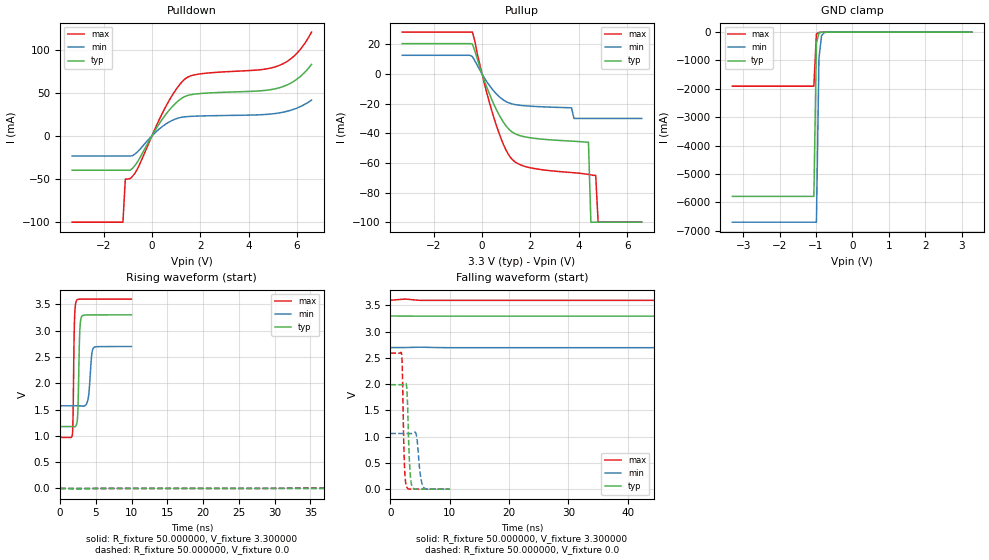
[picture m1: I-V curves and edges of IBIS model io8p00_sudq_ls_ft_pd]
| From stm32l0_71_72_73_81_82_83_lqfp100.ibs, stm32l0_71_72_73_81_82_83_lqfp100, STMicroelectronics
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|   Model io8p00_sudq_ls_ft_pd
[Model]  io8p00_sudq_ls_ft_pd
Model_type I/O
Polarity   Non-Inverting
Enable   Active-Low
Vinl =   0.990000V
Vinh =   2.310000V
Vmeas =  1.650000V
Cref =   50.000000pF
Rref =   100.000000M
Vref =   0.0V
C_comp   2.343000pF   2.309800pF   2.393900pF
[Temperature Range]   25.000000   0.125000k   -40.000000
[Pullup Reference]   3.300000V   2.700000V   3.600000V
[Pulldown Reference]   0.0V   0.0V   0.0V
[POWER Clamp Reference]   3.300000V   2.700000V   3.600000V
[GND Clamp Reference]   0.0V   0.0V   0.0V
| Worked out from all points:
|   slope of the pulldown table from 0 to 0.495 V, typ, clamps not added: 22.6 ohm
|   slope of the pullup table from 0 to 0.495 V, typ, clamps not added: 23.9 ohm
|   GND clamp passes 1 mA (typ) near -0.64 V on its own axis
|   rising waveform, R_fixture 50.000000, V_fixture 3.300000: 20-80 % time 207ps typ, 362ps min, 164ps max; typ from 1.18 V to 3.3 V
|   rising waveform, R_fixture 50.000000, V_fixture 0.0: 20-80 % time 205ns typ, 426ns min, 99.7ns max; typ from 0 V to 1.99 V
|   falling waveform, R_fixture 50.000000, V_fixture 3.300000: 20-80 % time 193ns typ, 381ns min, 106ns max; typ from 3.3 V to 1.18 V
|   falling waveform, R_fixture 50.000000, V_fixture 0.0: 20-80 % time 379ps typ, 551ps min, 301ps max; typ from 1.99 V to 0 V
[Pulldown]
|Voltage   I(typ)   I(min)   I(max)
-3.3V     -39.8mA    -23.38mA   -100mA
-1.2V     -39.8mA    -23.38mA   -100mA
-1.1V     -39.8mA    -23.38mA   -50.11mA
-900mV    -39.8mA    -23.38mA   -49.43mA
-700mV    -34.25mA   -21mA      -43.13mA
600mV     25.84mA    14.18mA    35.34mA
1V        38.32mA    19.82mA    53.81mA
1.4V      46.09mA    22.19mA    66.63mA
2V        49.05mA    23.02mA    71.83mA
5.2V      55.23mA    26.32mA    80.92mA
6V        65.76mA    32.26mA    95.84mA
6.6V      82.81mA    41.43mA    120.2mA
[Pullup]
|Voltage   I(typ)   I(min)   I(max)
-3.3V     20.5mA     12.63mA    28.27mA
-400mV    20.25mA    11.77mA    28.27mA
500mV     -20.88mA   -11.78mA   -30.07mA
1.2V      -38.62mA   -19.99mA   -56.79mA
1.9V      -42.8mA    -21.61mA   -62.92mA
3.7V      -45.29mA   -22.8mA    -66.5mA
3.8V      -45.39mA   -30mA      -66.64mA
4.4V      -46mA      -30mA      -67.77mA
4.5V      -100mA     -30mA      -68.06mA
4.7V      -100mA     -30mA      -68.41mA
4.8V      -100mA     -30mA      -100mA
6.6V      -100mA     -30mA      -100mA
[GND_clamp]
|Voltage   I(typ)   I(min)   I(max)
-3.3V     -5.787A    -6.696A    -1.906A
-1.06V    -5.787A    -6.696A    -1.906A
-990mV    -393.4mA   -6.696A    -70.76mA
-920mV    -33.04mA   -919.4mA   -10.91mA
-850mV    -6.842mA   -131.3mA   -6.529mA
-780mV    -3.49mA    -21.08mA   -4.216mA
3.28V     73.94uA    88.61uA    51.47uA
[POWER_clamp]
|Voltage   I(typ)   I(min)   I(max)
-3.28V    0A         0A         0A
0V        0A         0A         0A
[Ramp]
| variable   typ   min   max
dV/dt_r  1.19406/0.20443u   0.61140/0.42773u   1.55520/99.59326n
dV/dt_f  1.27242/0.19294u   0.63606/0.38172u   1.57766/0.10605u
R_load = 50.000000
[Rising Waveform]
R_fixture= 50.000000
V_fixture= 3.300000
V_fixture_min= 2.700000
V_fixture_max= 3.600000
|time   V(typ)   V(min)   V(max)
0s        1.176V     1.571V     970mV
1.702ns   1.176V     1.571V     1.017V
2.002ns   1.172V     1.571V     3.17V
2.282ns   1.213V     1.571V     3.57V
2.482ns   1.498V     1.571V     3.593V
2.743ns   2.977V     1.569V     3.597V
3.023ns   3.27V      1.566V     3.598V
3.904ns   3.298V     1.7V       3.599V
4.665ns   3.298V     2.67V      3.599V
9.97ns    3.299V     2.698V     3.599V
[Rising Waveform]
R_fixture= 50.000000
V_fixture= 0.0
V_fixture_min= 0.0
V_fixture_max= 0.0
|time   V(typ)   V(min)   V(max)
0s        1.995nV    14.14nV    4.364nV
50.05ns   270.4uV    -21.95uV   84.32mV
102.6ns   83.63mV    140.7uV    950.6mV
165.2ns   449.5mV    2.92mV     1.927V
205.2ns   740.5mV    17.3mV     2.287V
255.3ns   1.082V     53.22mV    2.483V
357.9ns   1.578V     187mV      2.573V
508ns     1.88V      446.8mV    2.591V
818.3ns   1.983V     866.7mV    2.592V
1.246us   1.99V      1.06V      2.592V
[Falling Waveform]
R_fixture= 50.000000
V_fixture= 3.300000
V_fixture_min= 2.700000
V_fixture_max= 3.600000
|time   V(typ)   V(min)   V(max)
0s        3.299V     2.698V     3.599V
85.09ns   3.296V     2.695V     3.473V
145.1ns   3.211V     2.695V     2.592V
212.7ns   2.848V     2.692V     1.602V
250.2ns   2.593V     2.681V     1.235V
285.3ns   2.344V     2.663V     1.089V
397.9ns   1.619V     2.542V     997.6mV
500.5ns   1.332V     2.372V     979.9mV
823.3ns   1.195V     1.797V     970.6mV
1.246us   1.176V     1.571V     970mV
[Falling Waveform]
R_fixture= 50.000000
V_fixture= 0.0
V_fixture_min= 0.0
V_fixture_max= 0.0
|time   V(typ)   V(min)   V(max)
0s        1.99V      1.06V      2.592V
1.922ns   1.99V      1.06V      2.564V
2.022ns   1.99V      1.06V      2.313V
2.382ns   1.995V     1.06V      480.1mV
2.783ns   1.915V     1.06V      38.06mV
3.243ns   503.8mV    1.06V      2.313mV
3.664ns   55.79mV    1.061V     212.5uV
4.404ns   969uV      1.024V     88.3uV
5.546ns   55.3uV     41.9mV     37.89uV
9.97ns    1.995nV    14.14nV    4.364nV
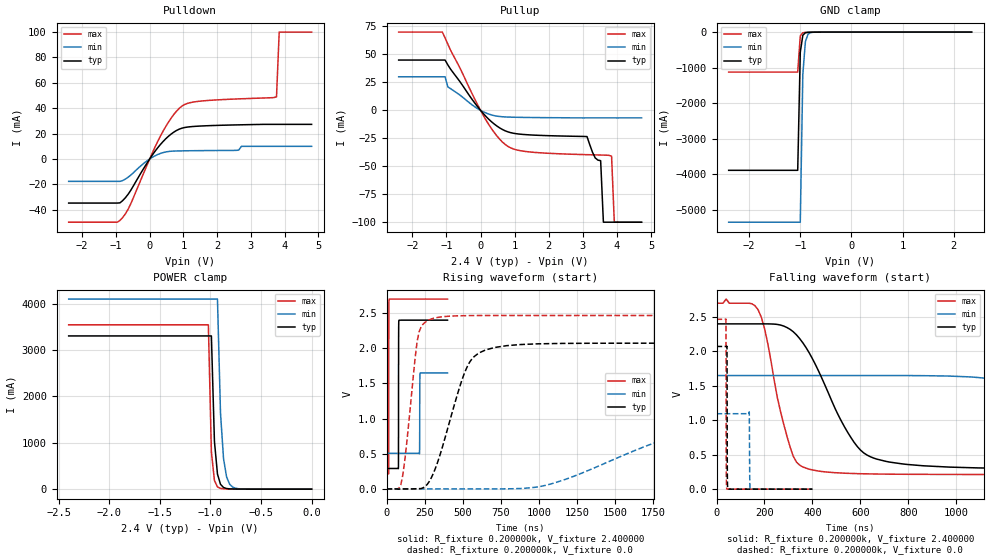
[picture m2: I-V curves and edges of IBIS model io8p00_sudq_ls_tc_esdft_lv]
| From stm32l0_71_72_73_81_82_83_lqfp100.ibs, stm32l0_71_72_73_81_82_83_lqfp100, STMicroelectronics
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|   Model io8p00_sudq_ls_tc_esdft_lv
[Model]  io8p00_sudq_ls_tc_esdft_lv
Model_type I/O
Polarity   Non-Inverting
Enable   Active-Low
Vinl =   0.720000V
Vinh =   1.680000V
Vmeas =  1.200000V
Cref =   50.000000pF
Rref =   100.000000M
Vref =   0.0V
C_comp   2.242700pF   2.201100pF   2.288600pF
[Temperature Range]   25.000000   0.105000k   -40.000000
[Pullup Reference]   2.400000V   1.650000V   2.700000V
[Pulldown Reference]   0.0V   0.0V   0.0V
[POWER Clamp Reference]   2.400000V   1.650000V   2.700000V
[GND Clamp Reference]   0.0V   0.0V   0.0V
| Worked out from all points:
|   slope of the pulldown table from 0 to 0.36 V, typ, clamps not added: 28.4 ohm
|   slope of the pullup table from 0 to 0.36 V, typ, clamps not added: 32.2 ohm
|   GND clamp passes 1 mA (typ) near -0.65 V on its own axis
|   POWER clamp passes 1 mA (typ) near -0.63 V on its own axis
|   rising waveform, R_fixture 0.200000k, V_fixture 2.400000: 20-80 % time 637ps typ, 857ps min, 664ps max; typ from 0.291 V to 2.4 V
|   rising waveform, R_fixture 0.200000k, V_fixture 0.0: 20-80 % time 173ns typ, 833ns min, 69.4ns max; typ from 0 V to 2.07 V
|   falling waveform, R_fixture 0.200000k, V_fixture 2.400000: 20-80 % time 181ns typ, 734ns min, 90.4ns max; typ from 2.4 V to 0.291 V
|   falling waveform, R_fixture 0.200000k, V_fixture 0.0: 20-80 % time 753ps typ, 1.18ns min, 666ps max; typ from 2.07 V to 0 V
[Pulldown]
|Voltage   I(typ)   I(min)   I(max)
-2.4V     -34.7mA    -17.62mA   -49.77mA
-880mV    -34.55mA   -17.62mA   -48.41mA
-560mV    -24.66mA   -12.69mA   -35.31mA
240mV     8.893mA    3.542mA    13.9mA
560mV     17.98mA    5.931mA    29.16mA
880mV     23.57mA    6.388mA    40.03mA
1.44V     25.89mA    6.593mA    45.41mA
2.64V     26.92mA    7mA        47.38mA
2.72V     26.96mA    10mA       47.46mA
3.76V     27.3mA     10mA       49mA
3.84V     27.3mA     10mA       100mA
4.8V      27.3mA     10mA       100mA
[Pullup]
|Voltage   I(typ)   I(min)   I(max)
-2.4V     45mA       30mA       70mA
-1.12V    45mA       30mA       70mA
-960mV    40.7mA     21mA       59.3mA
80mV      -2.838mA   -1.261mA   -4.478mA
800mV     -19.2mA    -5.978mA   -32.18mA
3.12V     -23.45mA   -6.7mA     -39.62mA
3.36V     -42.52mA   -6.7mA     -39.81mA
3.52V     -45mA      -6.7mA     -39.93mA
3.6V      -100mA     -6.7mA     -40mA
3.84V     -100mA     -6.7mA     -41mA
3.92V     -100mA     -6.7mA     -100mA
4.72V     -100mA     -6.7mA     -100mA
[GND_clamp]
|Voltage   I(typ)   I(min)   I(max)
-2.4V     -3.892A    -5.353A    -1.127A
-1.05V    -3.892A    -5.353A    -1.127A
-1V       -568.8mA   -5.353A    -105.4mA
-950mV    -88.95mA   -1.19A     -18.03mA
-900mV    -18.15mA   -269.2mA   -8.959mA
-850mV    -6.699mA   -63.45mA   -6.568mA
-800mV    -4.014mA   -16.61mA   -4.858mA
-650mV    -1.043mA   -1.218mA   -1.146mA
2.35V     0A         0A         0A
[POWER_clamp]
|Voltage   I(typ)   I(min)   I(max)
-2.4V     3.303A     4.097A     3.542A
-1.02V    3.303A     4.097A     3.542A
-990mV    3.303A     4.097A     802.4mA
-960mV    1.032A     4.097A     186.5mA
-930mV    325.2mA    4.097A     47.59mA
-900mV    104.8mA    1.637A     15.78mA
-870mV    35.83mA    655.7mA    8.015mA
-840mV    13.93mA    263.9mA    5.668mA
-810mV    6.712mA    107.2mA    4.56mA
-780mV    4.088mA    44.39mA    3.763mA
-690mV    1.741mA    4.361mA    1.91mA
0V        0A         0A         0A
[Ramp]
| variable   typ   min   max
dV/dt_r  0.65070/0.30842u   0.18995/0.83378u   1.03800/0.14875u
dV/dt_f  0.75696/0.32400u   0.19686/0.85250u   1.13786/0.16130u
R_load = 50.000000
[Rising Waveform]
R_fixture= 0.200000k
V_fixture= 2.400000
V_fixture_min= 1.650000
V_fixture_max= 2.700000
|time   V(typ)   V(min)   V(max)
0s        290.7mV    506.7mV    213mV
14.01ns   290.7mV    506.7mV    220.7mV
15.22ns   290.7mV    506.7mV    2.507V
16.82ns   290.7mV    506.7mV    2.694V
77.68ns   288.7mV    506.7mV    2.7V
79.28ns   2.144V     506.7mV    2.7V
81.28ns   2.397V     506.7mV    2.7V
215.8ns   2.4V       498.6mV    2.7V
220.2ns   2.4V       1.646V     2.7V
400ns     2.4V       1.65V      2.7V
[Rising Waveform]
R_fixture= 0.200000k
V_fixture= 0.0
V_fixture_min= 0.0
V_fixture_max= 0.0
|time   V(typ)   V(min)   V(max)
0s        1.569nV    9.966nV    1.195nV
93.43ns   -81.25uV   9.966nV    57.41mV
213.5ns   3.816mV    -11.57uV   2.233V
293.6ns   158.6mV    -17.9uV    2.417V
373.7ns   650mV      -17.76uV   2.45V
560.6ns   1.849V     10.44uV    2.465V
880.9ns   2.053V     6.203mV    2.467V
2.135us   2.072V     891.1mV    2.467V
3.016us   2.072V     1.069V     2.467V
13.33us   2.072V     1.095V     2.467V
[Falling Waveform]
R_fixture= 0.200000k
V_fixture= 2.400000
V_fixture_min= 1.650000
V_fixture_max= 2.700000
|time   V(typ)   V(min)   V(max)
0s        2.4V       1.65V      2.7V
173.5ns   2.4V       1.65V      2.605V
320.3ns   2.285V     1.65V      476.7mV
493.8ns   1.177V     1.65V      239.3mV
613.9ns   526.9mV    1.65V      223.2mV
787.5ns   361.6mV    1.649V     216.2mV
1.348us   297.3mV    1.505V     213.1mV
2.216us   290.8mV    722.1mV    213mV
3.056us   290.7mV    545.8mV    213mV
13.33us   290.7mV    506.7mV    213mV
[Falling Waveform]
R_fixture= 0.200000k
V_fixture= 0.0
V_fixture_min= 0.0
V_fixture_max= 0.0
|time   V(typ)   V(min)   V(max)
0s        2.072V     1.095V     2.467V
39.24ns   2.072V     1.095V     2.47V
40.44ns   2.072V     1.095V     427.7mV
42.84ns   2.072V     1.095V     5.71mV
43.64ns   2.071V     1.095V     1.912mV
45.25ns   162.9mV    1.095V     770.6uV
47.25ns   4.765mV    1.095V     330.4uV
136.5ns   12.52uV    1.12V      131.6uV
141.3ns   12.84uV    1.603mV    132.3uV
400ns     1.569nV    9.966nV    1.195nV
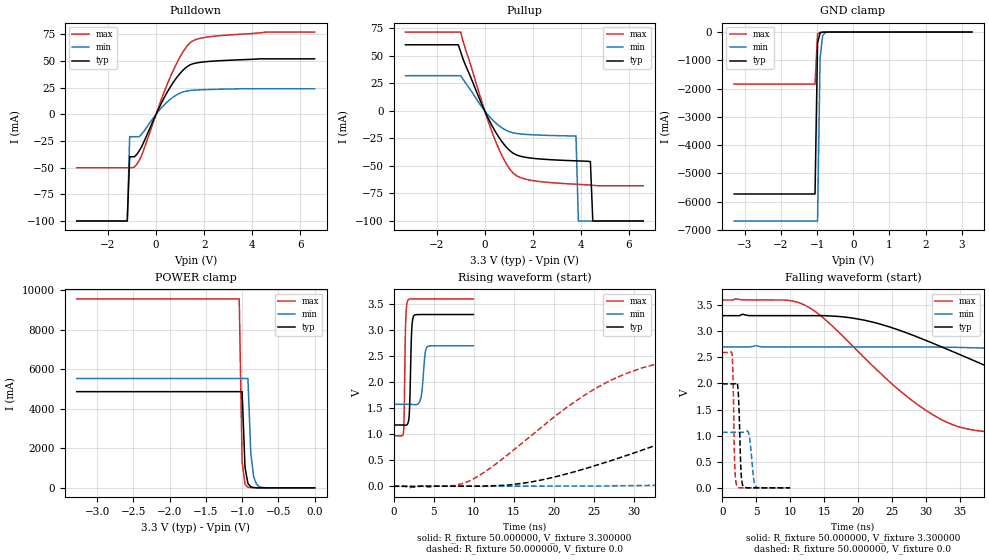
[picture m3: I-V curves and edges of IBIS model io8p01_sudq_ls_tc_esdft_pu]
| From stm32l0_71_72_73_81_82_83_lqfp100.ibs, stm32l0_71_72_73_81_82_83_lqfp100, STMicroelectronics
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|   Model io8p01_sudq_ls_tc_esdft_pu
[Model]  io8p01_sudq_ls_tc_esdft_pu
Model_type I/O
Polarity   Non-Inverting
Enable   Active-Low
Vinl =   0.990000V
Vinh =   2.310000V
Vmeas =  1.650000V
Cref =   50.000000pF
Rref =   100.000000M
Vref =   0.0V
C_comp   2.248300pF   2.207300pF   2.311900pF
[Temperature Range]   25.000000   0.125000k   -40.000000
[Pullup Reference]   3.300000V   2.700000V   3.600000V
[Pulldown Reference]   0.0V   0.0V   0.0V
[POWER Clamp Reference]   3.300000V   2.700000V   3.600000V
[GND Clamp Reference]   0.0V   0.0V   0.0V
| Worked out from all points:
|   slope of the pulldown table from 0 to 0.495 V, typ, clamps not added: 22.6 ohm
|   slope of the pullup table from 0 to 0.495 V, typ, clamps not added: 23.9 ohm
|   GND clamp passes 1 mA (typ) near -0.64 V on its own axis
|   POWER clamp passes 1 mA (typ) near -0.63 V on its own axis
|   rising waveform, R_fixture 50.000000, V_fixture 3.300000: 20-80 % time 209ps typ, 363ps min, 164ps max; typ from 1.18 V to 3.3 V
|   rising waveform, R_fixture 50.000000, V_fixture 0.0: 20-80 % time 27.8ns typ, 60.6ns min, 14.1ns max; typ from 0.001 V to 1.99 V
|   falling waveform, R_fixture 50.000000, V_fixture 3.300000: 20-80 % time 24.5ns typ, 54ns min, 13.4ns max; typ from 3.3 V to 1.18 V
|   falling waveform, R_fixture 50.000000, V_fixture 0.0: 20-80 % time 290ps typ, 460ps min, 227ps max; typ from 1.99 V to 0.001 V
[Pulldown]
|Voltage   I(typ)   I(min)   I(max)
-3.3V     -100mA     -100mA     -50.11mA
-1.2V     -100mA     -100mA     -50.11mA
-1.1V     -39.8mA    -21mA      -50.11mA
-900mV    -39.8mA    -21mA      -49.43mA
-600mV    -30.26mA   -18.59mA   -38.38mA
500mV     22.11mA    12.28mA    30.06mA
900mV     35.58mA    18.71mA    49.62mA
1.3V      44.74mA    21.88mA    64.23mA
1.7V      48.13mA    22.72mA    70.3mA
2.4V      49.79mA    23.31mA    73.03mA
4.6V      51.9mA     23.82mA    77mA
6.6V      51.9mA     23.82mA    77mA
[Pullup]
|Voltage   I(typ)   I(min)   I(max)
-3.3V     60mA       32mA       71.6mA
-1.1V     60mA       32mA       71.6mA
-1V       53.5mA     32mA       71.6mA
-100mV    4.893mA    2.926mA    6.861mA
400mV     -17.21mA   -9.813mA   -24.69mA
900mV     -32.92mA   -17.72mA   -48.15mA
1.3V      -39.75mA   -20.41mA   -58.47mA
3.8V      -45.36mA   -22.8mA    -66.6mA
3.9V      -45.44mA   -100mA     -66.72mA
4.4V      -46mA      -100mA     -67.4mA
4.5V      -100mA     -100mA     -67.56mA
6.6V      -100mA     -100mA     -68mA
[GND_clamp]
|Voltage   I(typ)   I(min)   I(max)
-3.3V     -5.732A    -6.688A    -1.842A
-1.06V    -5.732A    -6.688A    -1.842A
-990mV    -389.4mA   -6.688A    -68.34mA
-920mV    -32.57mA   -918.2mA   -10.72mA
-850mV    -6.763mA   -131mA     -6.509mA
-780mV    -3.471mA   -21mA      -4.208mA
3.28V     0A         0A         0A
[POWER_clamp]
|Voltage   I(typ)   I(min)   I(max)
-3.28V    4.87A      5.538A     9.569A
-1.04V    4.87A      5.538A     9.569A
-1V       4.87A      5.538A     1.315A
-960mV    1.032A     5.538A     186.5mA
-920mV    222.2mA    5.538A     31.65mA
-880mV    50.75mA    1.734A     9.59mA
-840mV    13.94mA    544.9mA    5.676mA
-800mV    5.568mA    172.7mA    4.284mA
-760mV    3.243mA    55.85mA    3.306mA
-680mV    1.609mA    7mA        1.749mA
0V        0A         0A         0A
[Ramp]
| variable   typ   min   max
dV/dt_r  1.19491/27.80577n   0.63556/60.63476n   1.55546/14.11873n
dV/dt_f  1.27326/24.47589n   0.66984/53.98609n   1.57747/13.38842n
R_load = 50.000000
[Rising Waveform]
R_fixture= 50.000000
V_fixture= 3.300000
V_fixture_min= 2.700000
V_fixture_max= 3.600000
|time   V(typ)   V(min)   V(max)
0s        1.178V     1.575V     970.9mV
1.241ns   1.177V     1.575V     1.046V
1.522ns   1.174V     1.575V     3.193V
1.782ns   1.209V     1.575V     3.573V
2.002ns   1.517V     1.575V     3.596V
2.262ns   2.989V     1.574V     3.599V
2.503ns   3.268V     1.571V     3.6V
3.383ns   3.299V     1.682V     3.6V
4.244ns   3.3V       2.683V     3.6V
9.97ns    3.3V       2.7V       3.6V
[Rising Waveform]
R_fixture= 50.000000
V_fixture= 0.0
V_fixture_min= 0.0
V_fixture_max= 0.0
|time   V(typ)   V(min)   V(max)
0s        1.075mV    1.827mV    669.2uV
9.009ns   3.398mV    4.367mV    73.51mV
17.02ns   78.74mV    4.376mV    950.8mV
27.03ns   486.7mV    8.328mV    2.027V
33.53ns   829.3mV    21.35mV    2.374V
42.04ns   1.231V     68.2mV     2.527V
59.06ns   1.722V     235.6mV    2.583V
79.58ns   1.924V     500.5mV    2.592V
144.1ns   1.992V     968.3mV    2.593V
249.2ns   1.993V     1.064V     2.593V
[Falling Waveform]
R_fixture= 50.000000
V_fixture= 3.300000
V_fixture_min= 2.700000
V_fixture_max= 3.600000
|time   V(typ)   V(min)   V(max)
0s        3.3V       2.7V       3.6V
12.01ns   3.3V       2.7V       3.51V
21.02ns   3.21V      2.7V       2.476V
29.53ns   2.847V     2.699V     1.521V
34.03ns   2.603V     2.693V     1.202V
39.54ns   2.294V     2.672V     1.065V
55.06ns   1.545V     2.548V     992.8mV
72.57ns   1.289V     2.319V     976.6mV
132.6ns   1.185V     1.71V      971mV
249.2ns   1.178V     1.575V     970.9mV
[Falling Waveform]
R_fixture= 50.000000
V_fixture= 0.0
V_fixture_min= 0.0
V_fixture_max= 0.0
|time   V(typ)   V(min)   V(max)
0s        1.993V     1.064V     2.593V
1.461ns   1.993V     1.064V     2.546V
1.842ns   1.994V     1.064V     448mV
2.162ns   2.017V     1.064V     36.64mV
2.402ns   1.724V     1.064V     6.285mV
2.763ns   322.2mV    1.064V     900.3uV
3.043ns   41.18mV    1.064V     616.8uV
3.944ns   1.139mV    1.018V     616.4uV
4.945ns   1.062mV    23.76mV    627uV
9.97ns    1.075mV    1.827mV    669.2uV
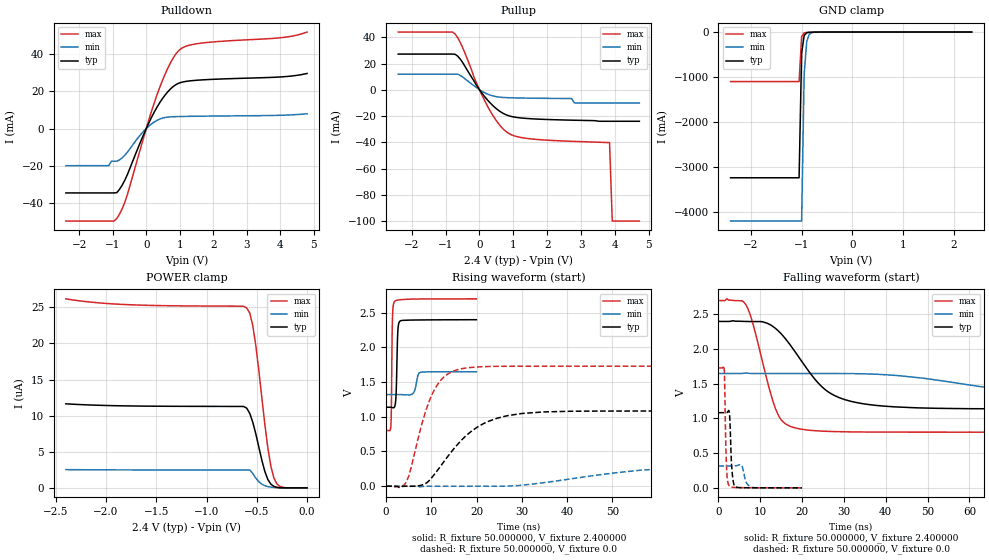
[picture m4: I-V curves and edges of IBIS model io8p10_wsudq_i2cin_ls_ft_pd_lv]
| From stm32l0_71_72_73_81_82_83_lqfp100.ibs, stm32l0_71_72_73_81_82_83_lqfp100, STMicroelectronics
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|   Model io8p10_wsudq_i2cin_ls_ft_pd_lv
[Model]  io8p10_wsudq_i2cin_ls_ft_pd_lv
Model_type I/O
Polarity   Non-Inverting
Enable   Active-Low
Vinl =   0.720000V
Vinh =   1.680000V
Vmeas =  1.200000V
Cref =   50.000000pF
Rref =   100.000000M
Vref =   0.0V
C_comp   2.943600pF   2.919700pF   2.965100pF
[Temperature Range]   25.000000   0.105000k   -40.000000
[Pullup Reference]   2.400000V   1.650000V   2.700000V
[Pulldown Reference]   0.0V   0.0V   0.0V
[POWER Clamp Reference]   2.400000V   1.650000V   2.700000V
[GND Clamp Reference]   0.0V   0.0V   0.0V
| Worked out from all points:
|   slope of the pulldown table from 0 to 0.36 V, typ, clamps not added: 28.5 ohm
|   slope of the pullup table from 0 to 0.36 V, typ, clamps not added: 32.2 ohm
|   GND clamp passes 1 mA (typ) near -0.64 V on its own axis
|   rising waveform, R_fixture 50.000000, V_fixture 2.400000: 20-80 % time 286ps typ, 638ps min, 195ps max; typ from 1.14 V to 2.4 V
|   rising waveform, R_fixture 50.000000, V_fixture 0.0: 20-80 % time 9.34ns typ, 24.6ns min, 4.82ns max; typ from 0 V to 1.08 V
|   falling waveform, R_fixture 50.000000, V_fixture 2.400000: 20-80 % time 10.1ns typ, 26.8ns min, 4.95ns max; typ from 2.4 V to 1.14 V
|   falling waveform, R_fixture 50.000000, V_fixture 0.0: 20-80 % time 482ps typ, 851ps min, 380ps max; typ from 1.08 V to 0 V
[Pulldown]
|Voltage   I(typ)   I(min)   I(max)
-2.4V     -34.7mA    -20mA      -49.82mA
-1.12V    -34.7mA    -20mA      -49.82mA
-1.04V    -34.7mA    -17.6mA    -49.82mA
-880mV    -34.55mA   -17.6mA    -48.46mA
-560mV    -24.65mA   -12.68mA   -35.33mA
0V        326fA      0A         140fA
400mV     13.84mA    5.066mA    22.03mA
720mV     21.25mA    6.254mA    35.26mA
1.04V     24.83mA    6.464mA    43.03mA
1.6V      26.11mA    6.627mA    45.88mA
4V        27.76mA    7.125mA    48.88mA
4.8V      29.63mA    7.94mA     51.96mA
[Pullup]
|Voltage   I(typ)   I(min)   I(max)
-2.4V     27.2mA     11.88mA    44.01mA
-720mV    27.06mA    11.88mA    42.53mA
-480mV    20.06mA    9.358mA    31.11mA
-160mV    6.59mA     3.051mA    9.467mA
240mV     -7.917mA   -3.299mA   -12.65mA
560mV     -15.67mA   -5.496mA   -25.76mA
880mV     -19.92mA   -6.062mA   -33.51mA
1.68V     -22.29mA   -6.449mA   -37.81mA
2.8V      -23.2mA    -10mA      -39.35mA
3.84V     -24mA      -10mA      -40.2mA
3.92V     -24mA      -10mA      -100mA
4.72V     -24mA      -10mA      -100mA
[GND_clamp]
|Voltage   I(typ)   I(min)   I(max)
-2.4V     -3.237A    -4.198A    -1.1A
-1.05V    -3.237A    -4.198A    -1.1A
-1V       -475.8mA   -4.198A    -104.2mA
-950mV    -76.26mA   -935.5mA   -18.4mA
-900mV    -16.62mA   -212.9mA   -9.114mA
-850mV    -6.559mA   -50.96mA   -6.598mA
-800mV    -4.01mA    -13.82mA   -4.868mA
-650mV    -1.055mA   -1.198mA   -1.154mA
2.35V     52.69uA    50.02uA    36.84uA
[POWER_clamp]
|Voltage   I(typ)   I(min)   I(max)
-2.4V     11.64uA    2.525uA    26.17uA
-1.86V    11.37uA    2.488uA    25.42uA
-600mV    11.04uA    2.474uA    24.9uA
-570mV    10.3uA     2.473uA    24.21uA
-540mV    9.097uA    2uA        22.48uA
-510mV    7.497uA    1.35uA     19.73uA
-450mV    3.845uA    512.5nA    12.52uA
-390mV    1.154uA    175.5nA    5.528uA
-360mV    508.2nA    102.8nA    2.997uA
-330mV    204.4nA    60.39nA    1.375uA
-270mV    0A         0A         194.9nA
0V        0A         0A         0A
[Ramp]
| variable   typ   min   max
dV/dt_r  0.65004/9.33128n   0.18968/24.62197n   1.03746/4.80805n
dV/dt_f  0.75702/10.04251n   0.19716/26.72500n   1.13800/4.93875n
R_load = 50.000000
[Rising Waveform]
R_fixture= 50.000000
V_fixture= 2.400000
V_fixture_min= 1.650000
V_fixture_max= 2.700000
|time   V(typ)   V(min)   V(max)
0s        1.137V     1.32V      802.9mV
1.041ns   1.137V     1.32V      867.8mV
1.161ns   1.136V     1.32V      1.179V
1.401ns   1.133V     1.32V      2.435V
1.842ns   1.142V     1.32V      2.66V
2.202ns   1.335V     1.32V      2.676V
2.603ns   2.257V     1.32V      2.683V
3.003ns   2.375V     1.32V      2.686V
7.648ns   2.395V     1.641V     2.698V
19.94ns   2.399V     1.649V     2.7V
[Rising Waveform]
R_fixture= 50.000000
V_fixture= 0.0
V_fixture_min= 0.0
V_fixture_max= 0.0
|time   V(typ)   V(min)   V(max)
0s        -519nV     -2.975uV   -282.8nV
4.505ns   -919.5uV   97.44uV    65.32mV
8.509ns   31.91mV    -948.9uV   1.034V
11.51ns   243mV      -199uV     1.48V
14.51ns   504.2mV    -200.8uV   1.648V
18.52ns   774.9mV    -157.7uV   1.71V
26.53ns   1.012V     1.743mV    1.728V
41.04ns   1.08V      107.8mV    1.729V
80.08ns   1.083V     301.8mV    1.729V
249.2ns   1.083V     316.1mV    1.729V
[Falling Waveform]
R_fixture= 50.000000
V_fixture= 2.400000
V_fixture_min= 1.650000
V_fixture_max= 2.700000
|time   V(typ)   V(min)   V(max)
0s        2.399V     1.649V     2.7V
6.507ns   2.399V     1.655V     2.644V
8.008ns   2.397V     1.649V     2.412V
14.01ns   2.279V     1.648V     1.086V
16.52ns   2.11V      1.648V     904.9mV
21.02ns   1.728V     1.648V     835.3mV
29.53ns   1.285V     1.648V     808.9mV
47.55ns   1.153V     1.59V      803.1mV
90.59ns   1.137V     1.348V     802.9mV
249.2ns   1.137V     1.32V      802.9mV
[Falling Waveform]
R_fixture= 50.000000
V_fixture= 0.0
V_fixture_min= 0.0
V_fixture_max= 0.0
|time   V(typ)   V(min)   V(max)
0s        1.083V     316.1mV    1.729V
1.321ns   1.083V     316.1mV    1.744V
1.441ns   1.083V     316.1mV    1.592V
1.722ns   1.083V     316.1mV    680.8mV
1.922ns   1.083V     316.1mV    307.5mV
2.523ns   1.107V     316.1mV    33.22mV
3.203ns   271.1mV    315.9mV    9.111mV
3.924ns   22.52mV    315.9mV    5.264mV
7.928ns   1.315mV    8.675mV    1.285mV
19.94ns   -519nV     -2.975uV   -282.8nV
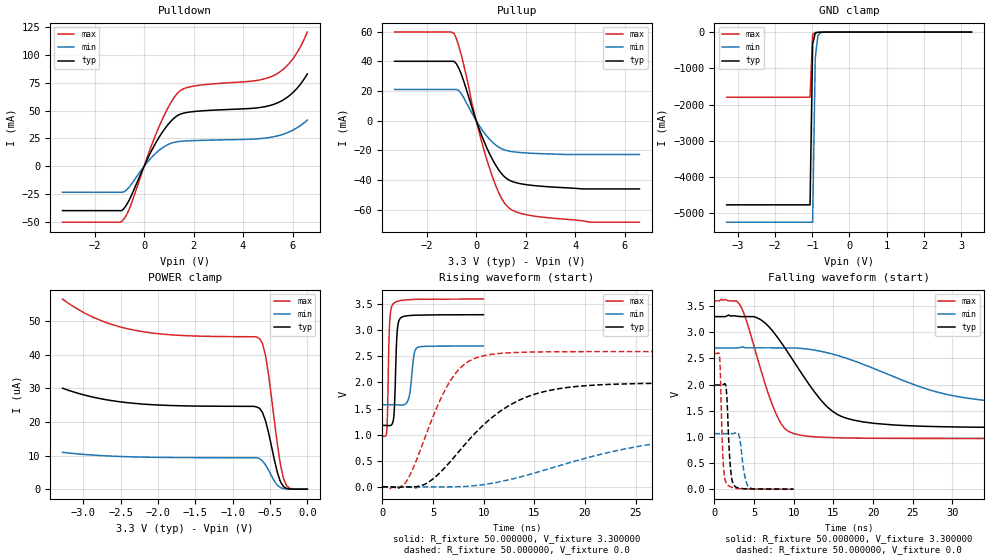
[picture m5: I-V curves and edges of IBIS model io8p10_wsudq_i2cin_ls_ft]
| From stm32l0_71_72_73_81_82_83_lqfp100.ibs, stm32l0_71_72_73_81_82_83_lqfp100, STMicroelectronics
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|   Model io8p10_wsudq_i2cin_ls_ft
[Model]  io8p10_wsudq_i2cin_ls_ft
Model_type I/O
Polarity   Non-Inverting
Enable   Active-Low
Vinl =   0.990000V
Vinh =   2.310000V
Vmeas =  1.650000V
Cref =   50.000000pF
Rref =   100.000000M
Vref =   0.0V
C_comp   3.020400pF   2.988300pF   3.054500pF
[Temperature Range]   25.000000   0.125000k   -40.000000
[Pullup Reference]   3.300000V   2.700000V   3.600000V
[Pulldown Reference]   0.0V   0.0V   0.0V
[POWER Clamp Reference]   3.300000V   2.700000V   3.600000V
[GND Clamp Reference]   0.0V   0.0V   0.0V
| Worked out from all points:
|   slope of the pulldown table from 0 to 0.495 V, typ, clamps not added: 22.6 ohm
|   slope of the pullup table from 0 to 0.495 V, typ, clamps not added: 23.9 ohm
|   GND clamp passes 1 mA (typ) near -0.64 V on its own axis
|   rising waveform, R_fixture 50.000000, V_fixture 3.300000: 20-80 % time 222ps typ, 368ps min, 183ps max; typ from 1.18 V to 3.3 V
|   rising waveform, R_fixture 50.000000, V_fixture 0.0: 20-80 % time 6.53ns typ, 13.6ns min, 3.47ns max; typ from 0 V to 1.99 V
|   falling waveform, R_fixture 50.000000, V_fixture 3.300000: 20-80 % time 5.96ns typ, 12.5ns min, 3.28ns max; typ from 3.3 V to 1.18 V
|   falling waveform, R_fixture 50.000000, V_fixture 0.0: 20-80 % time 405ps typ, 573ps min, 328ps max; typ from 1.99 V to 0 V
[Pulldown]
|Voltage   I(typ)   I(min)   I(max)
-3.3V     -39.83mA   -23.37mA   -50.21mA
-900mV    -39.83mA   -23.37mA   -49.53mA
-600mV    -30.28mA   -18.59mA   -38.45mA
500mV     22.11mA    12.28mA    30.1mA
1V        38.33mA    19.81mA    53.88mA
1.4V      46.1mA     22.18mA    66.72mA
2V        49.07mA    23.02mA    71.93mA
4.4V      52.05mA    24.38mA    76.53mA
5.2V      55.25mA    26.31mA    81.02mA
5.6V      59.18mA    28.57mA    86.57mA
6V        65.79mA    32.24mA    95.97mA
6.6V      82.83mA    41.41mA    120.4mA
[Pullup]
|Voltage   I(typ)   I(min)   I(max)
-3.3V     40.03mA    21.09mA    59.71mA
-900mV    40.03mA    21.09mA    58.93mA
-800mV    38.38mA    21.09mA    55.25mA
-600mV    31.19mA    18.17mA    44.03mA
0V        90fA       25.26pA    0A
500mV     -20.88mA   -11.78mA   -30.07mA
900mV     -32.92mA   -17.72mA   -48.15mA
1.3V      -39.75mA   -20.41mA   -58.47mA
1.8V      -42.5mA    -21.48mA   -62.49mA
2.7V      -44.27mA   -22.29mA   -65.04mA
4.6V      -46mA      -22.8mA    -68.41mA
6.6V      -46mA      -22.8mA    -68.41mA
[GND_clamp]
|Voltage   I(typ)   I(min)   I(max)
-3.3V     -4.766A    -5.244A    -1.797A
-1.06V    -4.766A    -5.244A    -1.797A
-990mV    -326.6mA   -5.244A    -67.9mA
-920mV    -28.92mA   -722.1mA   -10.96mA
-850mV    -6.612mA   -104.2mA   -6.532mA
-780mV    -3.464mA   -17.27mA   -4.209mA
-500mV    -57.88uA   -167.8uA   -34.02uA
3.28V     0A         0A         0A
[POWER_clamp]
|Voltage   I(typ)   I(min)   I(max)
-3.28V    30.07uA    10.97uA    56.59uA
-2.84V    27.25uA    10.1uA     50.89uA
-2.32V    25.55uA    9.602uA    47.34uA
-640mV    24.06uA    9.099uA    44.84uA
-600mV    22.76uA    8.364uA    43.37uA
-560mV    20.32uA    7.211uA    39.74uA
-520mV    16.86uA    5.675uA    34.14uA
-400mV    4.841uA    1.145uA    13.1uA
-360mV    2.184uA    477.2nA    7.288uA
-320mV    772.4nA    180.3nA    3.213uA
-240mV    60.03nA    0A         295.3nA
0V        0A         0A         0A
[Ramp]
| variable   typ   min   max
dV/dt_r  1.19496/6.51931n   0.62946/13.56635n   1.55568/3.46885n
dV/dt_f  1.27374/5.95545n   0.65328/12.43069n   1.57856/3.27260n
R_load = 50.000000
[Rising Waveform]
R_fixture= 50.000000
V_fixture= 3.300000
V_fixture_min= 2.700000
V_fixture_max= 3.600000
|time   V(typ)   V(min)   V(max)
0s        1.177V     1.573V     969mV
440.4ps   1.176V     1.573V     1.075V
700.7ps   1.173V     1.573V     3.073V
1.041ns   1.243V     1.574V     3.502V
1.201ns   1.568V     1.574V     3.53V
1.461ns   2.967V     1.572V     3.555V
1.782ns   3.234V     1.568V     3.572V
2.603ns   3.283V     1.697V     3.587V
3.443ns   3.291V     2.67V      3.595V
9.97ns    3.3V       2.7V       3.6V
[Rising Waveform]
R_fixture= 50.000000
V_fixture= 0.0
V_fixture_min= 0.0
V_fixture_max= 0.0
|time   V(typ)   V(min)   V(max)
0s        414.2nV    -6.235uV   358.7uV
2.302ns   -2.261mV   -1.621mV   82.67mV
4.204ns   48.77mV    -950.7uV   940.6mV
6.507ns   439.4mV    -602.9uV   1.967V
8.008ns   780.2mV    5.188mV    2.335V
9.71ns    1.136V     34.31mV    2.5V
13.91ns   1.696V     204mV      2.58V
18.82ns   1.917V     480.9mV    2.591V
30.83ns   1.989V     922.3mV    2.593V
49.85ns   1.992V     1.062V     2.593V
[Falling Waveform]
R_fixture= 50.000000
V_fixture= 3.300000
V_fixture_min= 2.700000
V_fixture_max= 3.600000
|time   V(typ)   V(min)   V(max)
0s        3.3V       2.7V       3.6V
3.203ns   3.301V     2.707V     3.524V
5.405ns   3.274V     2.703V     2.513V
7.508ns   2.991V     2.702V     1.534V
8.609ns   2.761V     2.701V     1.207V
9.91ns    2.464V     2.7V       1.067V
14.21ns   1.575V     2.608V     988.4mV
17.52ns   1.321V     2.457V     976.5mV
30.33ns   1.19V      1.78V      969.4mV
49.85ns   1.177V     1.573V     969mV
[Falling Waveform]
R_fixture= 50.000000
V_fixture= 0.0
V_fixture_min= 0.0
V_fixture_max= 0.0
|time   V(typ)   V(min)   V(max)
0s        1.992V     1.062V     2.593V
640.6ps   1.992V     1.062V     2.541V
1.081ns   1.996V     1.062V     571.4mV
1.522ns   1.855V     1.062V     107.5mV
1.982ns   478.2mV    1.061V     48.25mV
2.482ns   69.48mV    1.067V     22.7mV
3.143ns   18.8mV     1.003V     9.924mV
3.744ns   8.715mV    312.7mV    7.281mV
4.384ns   4.99mV     32.62mV    3.899mV
9.97ns    414.2nV    -6.235uV   358.7uV
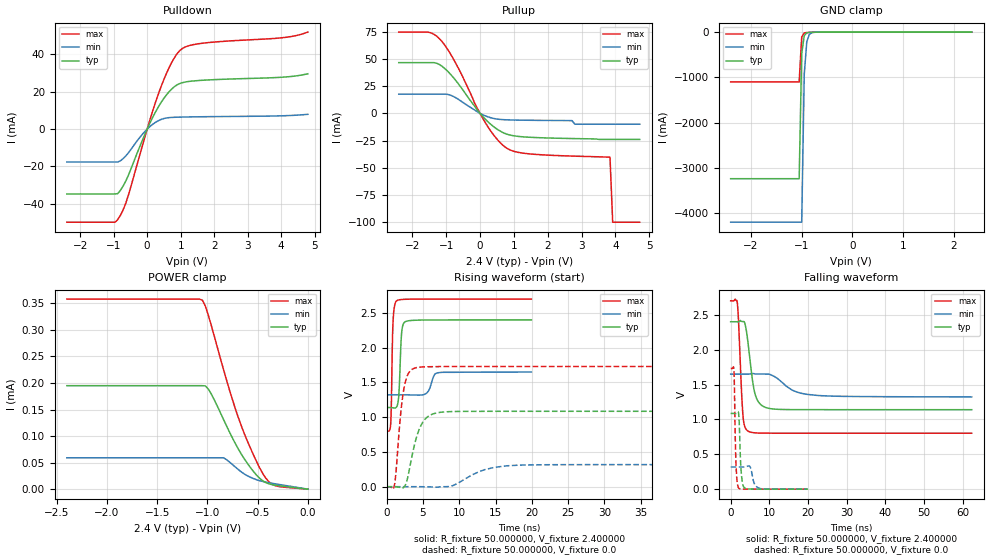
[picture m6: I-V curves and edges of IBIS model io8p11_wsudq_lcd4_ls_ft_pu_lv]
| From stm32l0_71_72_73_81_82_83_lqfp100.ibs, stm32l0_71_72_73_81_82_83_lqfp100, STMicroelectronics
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|   Model io8p11_wsudq_lcd4_ls_ft_pu_lv
[Model]  io8p11_wsudq_lcd4_ls_ft_pu_lv
Model_type I/O
Polarity   Non-Inverting
Enable   Active-Low
Vinl =   0.720000V
Vinh =   1.680000V
Vmeas =  1.200000V
Cref =   50.000000pF
Rref =   100.000000M
Vref =   0.0V
C_comp   3.178800pF   3.170000pF   3.206700pF
[Temperature Range]   25.000000   0.105000k   -40.000000
[Pullup Reference]   2.400000V   1.650000V   2.700000V
[Pulldown Reference]   0.0V   0.0V   0.0V
[POWER Clamp Reference]   2.400000V   1.650000V   2.700000V
[GND Clamp Reference]   0.0V   0.0V   0.0V
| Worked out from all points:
|   slope of the pulldown table from 0 to 0.36 V, typ, clamps not added: 28.5 ohm
|   slope of the pullup table from 0 to 0.36 V, typ, clamps not added: 32.2 ohm
|   GND clamp passes 1 mA (typ) near -0.64 V on its own axis
|   rising waveform, R_fixture 50.000000, V_fixture 2.400000: 20-80 % time 299ps typ, 645ps min, 214ps max; typ from 1.14 V to 2.4 V
|   rising waveform, R_fixture 50.000000, V_fixture 0.0: 20-80 % time 1.6ns typ, 3.83ns min, 942ps max; typ from 0.001 V to 1.09 V
|   falling waveform, R_fixture 50.000000, V_fixture 2.400000: 20-80 % time 1.81ns typ, 5.25ns min, 919ps max; typ from 2.4 V to 1.14 V
|   falling waveform, R_fixture 50.000000, V_fixture 0.0: 20-80 % time 500ps typ, 878ps min, 401ps max; typ from 1.09 V to 0.001 V
[Pulldown]
|Voltage   I(typ)   I(min)   I(max)
-2.4V     -34.7mA    -17.6mA    -49.82mA
-960mV    -34.7mA    -17.6mA    -49.82mA
-880mV    -34.55mA   -17.6mA    -48.46mA
-720mV    -30.52mA   -15.8mA    -43.27mA
-560mV    -24.65mA   -12.68mA   -35.33mA
0V        0A         0A         0A
400mV     13.84mA    5.066mA    22.03mA
720mV     21.25mA    6.254mA    35.26mA
1.04V     24.83mA    6.464mA    43.02mA
1.6V      26.11mA    6.627mA    45.88mA
4V        27.76mA    7.125mA    48.87mA
4.8V      29.63mA    7.94mA     51.96mA
[Pullup]
|Voltage   I(typ)   I(min)   I(max)
-2.4V     46.57mA    17.6mA     74.62mA
-1.52V    46.57mA    17.6mA     74.51mA
-1.2V     44.84mA    17.6mA     68.64mA
-720mV    30.34mA    14.43mA    46.24mA
-160mV    6.617mA    3.074mA    9.467mA
160mV     -5.477mA   -2.361mA   -8.695mA
480mV     -14.04mA   -5.167mA   -22.91mA
800mV     -19.21mA   -5.978mA   -32.18mA
1.52V     -22.07mA   -6.4mA     -37.42mA
3.84V     -24mA      -10mA      -40.2mA
3.92V     -24mA      -10mA      -100mA
4.72V     -24mA      -10mA      -100mA
[GND_clamp]
|Voltage   I(typ)   I(min)   I(max)
-2.4V     -3.238A    -4.199A    -1.101A
-1.05V    -3.238A    -4.199A    -1.101A
-1V       -476.5mA   -4.199A    -104.7mA
-950mV    -76.68mA   -936.1mA   -18.74mA
-900mV    -16.85mA   -213.2mA   -9.358mA
-850mV    -6.706mA   -51.12mA   -6.778mA
-800mV    -4.108mA   -13.92mA   -4.995mA
-650mV    -1.07mA    -1.211mA   -1.175mA
2.35V     0A         0A         0A
[POWER_clamp]
|Voltage   I(typ)   I(min)   I(max)
-2.4V     195uA      59.14uA    358.2uA
-1.05V    195uA      59.14uA    356uA
-1.02V    194.5uA    59.14uA    344.5uA
-960mV    178.7uA    59.14uA    307.4uA
-840mV    131.4uA    59.14uA    225.5uA
-690mV    74.82uA    36.58uA    133.7uA
-600mV    48.08uA    24.92uA    89.53uA
-510mV    26.23uA    17.69uA    51.64uA
-450mV    15.91uA    14.53uA    29.77uA
-390mV    10.19uA    12.23uA    14.39uA
-330mV    7.608uA    10.25uA    6.963uA
0V        0A         0A         0A
[Ramp]
| variable   typ   min   max
dV/dt_r  0.65095/1.59502n   0.19036/3.82920n   1.03799/0.93836n
dV/dt_f  0.75618/1.81084n   0.19410/5.23178n   1.13779/0.91616n
R_load = 50.000000
[Rising Waveform]
R_fixture= 50.000000
V_fixture= 2.400000
V_fixture_min= 1.650000
V_fixture_max= 2.700000
|time   V(typ)   V(min)   V(max)
0s        1.14V      1.323V     802.6mV
560.6ps   1.139V     1.323V     918.7mV
880.9ps   1.135V     1.323V     2.384V
1.361ns   1.149V     1.323V     2.674V
1.682ns   1.337V     1.323V     2.688V
2.082ns   2.237V     1.323V     2.694V
2.523ns   2.372V     1.323V     2.696V
5.365ns   2.399V     1.337V     2.7V
7.207ns   2.4V       1.642V     2.7V
19.94ns   2.4V       1.65V      2.7V
[Rising Waveform]
R_fixture= 50.000000
V_fixture= 0.0
V_fixture_min= 0.0
V_fixture_max= 0.0
|time   V(typ)   V(min)   V(max)
0s        878.3uV    1.336mV    737.3uV
1.001ns   990uV      1.333mV    -9.969mV
2.002ns   -15.84mV   1.327mV    1.129V
2.377ns   -5.157mV   1.343mV    1.415V
3.003ns   186.2mV    1.405mV    1.632V
4.004ns   674.9mV    1.414mV    1.711V
5.38ns    981.9mV    -141.6uV   1.725V
8.008ns   1.077V     1.428mV    1.729V
16.64ns   1.086V     302.2mV    1.73V
62.31ns   1.086V     318.6mV    1.73V
[Falling Waveform]
R_fixture= 50.000000
V_fixture= 2.400000
V_fixture_min= 1.650000
V_fixture_max= 2.700000
|time   V(typ)   V(min)   V(max)
0s        2.4V       1.65V      2.7V
1.752ns   2.4V       1.65V      2.657V
2.878ns   2.404V     1.65V      1.324V
3.253ns   2.403V     1.65V      1.015V
3.879ns   2.328V     1.65V      869.4mV
4.63ns    2.031V     1.65V      829mV
6.381ns   1.35V      1.652V     807.6mV
9.384ns   1.166V     1.65V      803.3mV
19.77ns   1.14V      1.359V     802.7mV
62.31ns   1.14V      1.323V     802.6mV
[Falling Waveform]
R_fixture= 50.000000
V_fixture= 0.0
V_fixture_min= 0.0
V_fixture_max= 0.0
|time   V(typ)   V(min)   V(max)
0s        1.086V     318.6mV    1.73V
840.8ps   1.086V     318.6mV    1.709V
1.201ns   1.085V     318.6mV    699.9mV
1.401ns   1.085V     318.6mV    336.6mV
2.042ns   1.09V      318.6mV    19.28mV
2.723ns   249.8mV    318.4mV    4.475mV
3.524ns   22.92mV    319.1mV    2.612mV
4.925ns   3.596mV    328.5mV    1.473mV
7.608ns   1.556mV    9.591mV    925uV
19.94ns   878.3uV    1.336mV    737.3uV
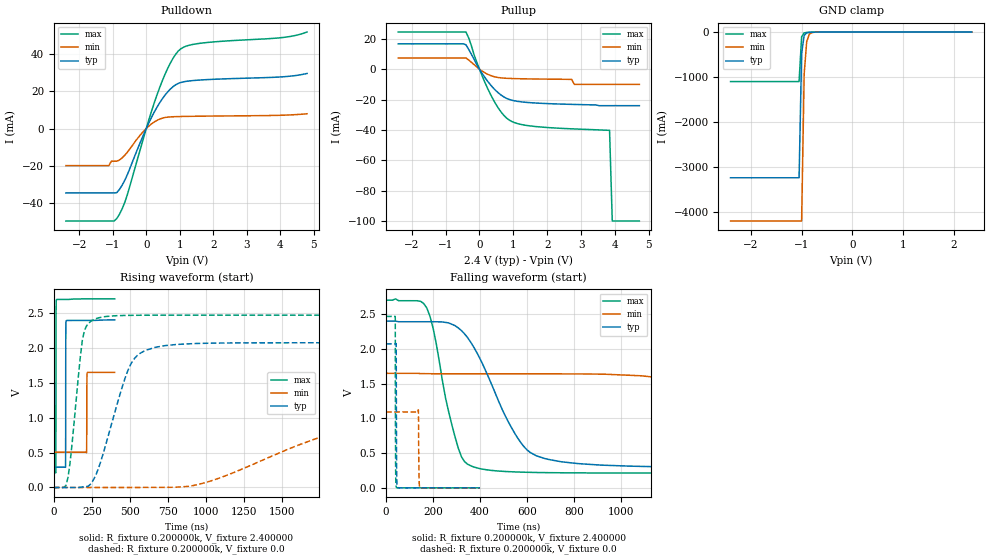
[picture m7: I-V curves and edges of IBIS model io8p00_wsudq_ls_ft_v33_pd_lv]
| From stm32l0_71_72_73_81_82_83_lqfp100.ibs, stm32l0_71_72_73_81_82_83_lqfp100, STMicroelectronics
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|   Model io8p00_wsudq_ls_ft_v33_pd_lv
[Model]  io8p00_wsudq_ls_ft_v33_pd_lv
Model_type I/O
Polarity   Non-Inverting
Enable   Active-Low
Vinl =   0.720000V
Vinh =   1.680000V
Vmeas =  1.200000V
Cref =   50.000000pF
Rref =   100.000000M
Vref =   0.0V
C_comp   2.582000pF   2.574200pF   2.601000pF
[Temperature Range]   25.000000   0.105000k   -40.000000
[Pullup Reference]   2.400000V   1.650000V   2.700000V
[Pulldown Reference]   0.0V   0.0V   0.0V
[POWER Clamp Reference]   2.400000V   1.650000V   2.700000V
[GND Clamp Reference]   0.0V   0.0V   0.0V
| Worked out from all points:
|   slope of the pulldown table from 0 to 0.36 V, typ, clamps not added: 28.5 ohm
|   slope of the pullup table from 0 to 0.36 V, typ, clamps not added: 32.2 ohm
|   GND clamp passes 1 mA (typ) near -0.64 V on its own axis
|   rising waveform, R_fixture 0.200000k, V_fixture 2.400000: 20-80 % time 676ps typ, 826ps min, 650ps max; typ from 0.291 V to 2.4 V
|   rising waveform, R_fixture 0.200000k, V_fixture 0.0: 20-80 % time 169ns typ, 818ns min, 66.4ns max; typ from 0 V to 2.07 V
|   falling waveform, R_fixture 0.200000k, V_fixture 2.400000: 20-80 % time 180ns typ, 730ns min, 89.8ns max; typ from 2.4 V to 0.291 V
|   falling waveform, R_fixture 0.200000k, V_fixture 0.0: 20-80 % time 1.2ns typ, 1.71ns min, 978ps max; typ from 2.07 V to 0 V
[Pulldown]
|Voltage   I(typ)   I(min)   I(max)
-2.4V     -34.7mA    -20mA      -49.82mA
-1.12V    -34.7mA    -20mA      -49.82mA
-1.04V    -34.7mA    -17.6mA    -49.82mA
-880mV    -34.55mA   -17.6mA    -48.46mA
-560mV    -24.65mA   -12.68mA   -35.33mA
0V        0A         0A         142fA
400mV     13.84mA    5.066mA    22.03mA
720mV     21.25mA    6.254mA    35.26mA
1.04V     24.83mA    6.464mA    43.03mA
1.6V      26.11mA    6.627mA    45.88mA
4V        27.76mA    7.125mA    48.88mA
4.8V      29.64mA    7.94mA     51.96mA
[Pullup]
|Voltage   I(typ)   I(min)   I(max)
-2.4V     16.75mA    7.419mA    24.5mA
-400mV    16.1mA     7.419mA    24.5mA
0V        0A         0A         0A
320mV     -10.16mA   -4.078mA   -16.34mA
640mV     -17.08mA   -5.718mA   -28.28mA
960mV     -20.45mA   -6.128mA   -34.5mA
1.76V     -22.39mA   -6.47mA    -37.97mA
2.72V     -23.16mA   -6.7mA     -39.27mA
2.8V      -23.2mA    -10mA      -39.35mA
3.84V     -24mA      -10mA      -40.2mA
3.92V     -24mA      -10mA      -100mA
4.72V     -24mA      -10mA      -100mA
[GND_clamp]
|Voltage   I(typ)   I(min)   I(max)
-2.4V     -3.237A    -4.198A    -1.1A
-1.05V    -3.237A    -4.198A    -1.1A
-1V       -475.9mA   -4.198A    -104.3mA
-950mV    -76.38mA   -935.5mA   -18.57mA
-900mV    -16.78mA   -213mA     -9.302mA
-850mV    -6.726mA   -51.1mA    -6.732mA
-800mV    -4.12mA    -13.96mA   -4.933mA
-650mV    -1.06mA    -1.216mA   -1.157mA
2.35V     52.69uA    50.02uA    36.84uA
[POWER_clamp]
|Voltage   I(typ)   I(min)   I(max)
-2.4V     0A         0A         0A
0V        0A         0A         0A
[Ramp]
| variable   typ   min   max
dV/dt_r  0.65004/0.30196u   0.18965/0.81405u   1.03746/0.14357u
dV/dt_f  0.75702/0.32158u   0.19716/0.84586u   1.13800/0.15969u
R_load = 50.000000
[Rising Waveform]
R_fixture= 0.200000k
V_fixture= 2.400000
V_fixture_min= 1.650000
V_fixture_max= 2.700000
|time   V(typ)   V(min)   V(max)
0s        290.6mV    505.5mV    212.8mV
13.21ns   290.6mV    505.5mV    211.4mV
14.41ns   290.6mV    505.5mV    2.257V
16.82ns   290.6mV    505.5mV    2.685V
76.88ns   288.7mV    505.5mV    2.691V
78.48ns   2.09V      505.5mV    2.691V
80.48ns   2.382V     505.5mV    2.691V
215ns     2.391V     500mV      2.699V
219.4ns   2.391V     1.642V     2.699V
400ns     2.399V     1.648V     2.699V
[Rising Waveform]
R_fixture= 0.200000k
V_fixture= 0.0
V_fixture_min= 0.0
V_fixture_max= 0.0
|time   V(typ)   V(min)   V(max)
0s        1.888nV    11.84nV    1.435nV
93.43ns   -107.3uV   11.84nV    147.8mV
200.2ns   10.21mV    11.84nV    2.241V
280.3ns   200.6mV    -23.39uV   2.418V
373.7ns   866.6mV    -23.5uV    2.453V
547.2ns   1.887V     186.4uV    2.465V
934.3ns   2.061V     36.52mV    2.466V
1.869us   2.071V     798.5mV    2.466V
2.776us   2.071V     1.055V     2.466V
13.33us   2.071V     1.091V     2.466V
[Falling Waveform]
R_fixture= 0.200000k
V_fixture= 2.400000
V_fixture_min= 1.650000
V_fixture_max= 2.700000
|time   V(typ)   V(min)   V(max)
0s        2.399V     1.648V     2.699V
160.2ns   2.389V     1.643V     2.651V
320.3ns   2.264V     1.64V      451.8mV
507.2ns   1.039V     1.64V      235.3mV
613.9ns   509.6mV    1.64V      222.8mV
814.1ns   350.2mV    1.639V     215.3mV
1.335us   297.3mV    1.498V     212.9mV
2.189us   290.8mV    722.3mV    212.8mV
2.936us   290.6mV    551.6mV    212.8mV
13.33us   290.6mV    505.5mV    212.8mV
[Falling Waveform]
R_fixture= 0.200000k
V_fixture= 0.0
V_fixture_min= 0.0
V_fixture_max= 0.0
|time   V(typ)   V(min)   V(max)
0s        2.071V     1.091V     2.466V
38.44ns   2.071V     1.091V     2.467V
40.44ns   2.071V     1.091V     260.8mV
42.84ns   2.06V      1.091V     15.6mV
43.64ns   1.013V     1.091V     7.458mV
45.25ns   112.8mV    1.091V     1.809mV
49.25ns   4.573mV    1.091V     171.6uV
137.3ns   16.84uV    1.122V     132.9uV
143.7ns   17.18uV    6.437mV    134.1uV
400ns     1.888nV    11.84nV    1.435nV
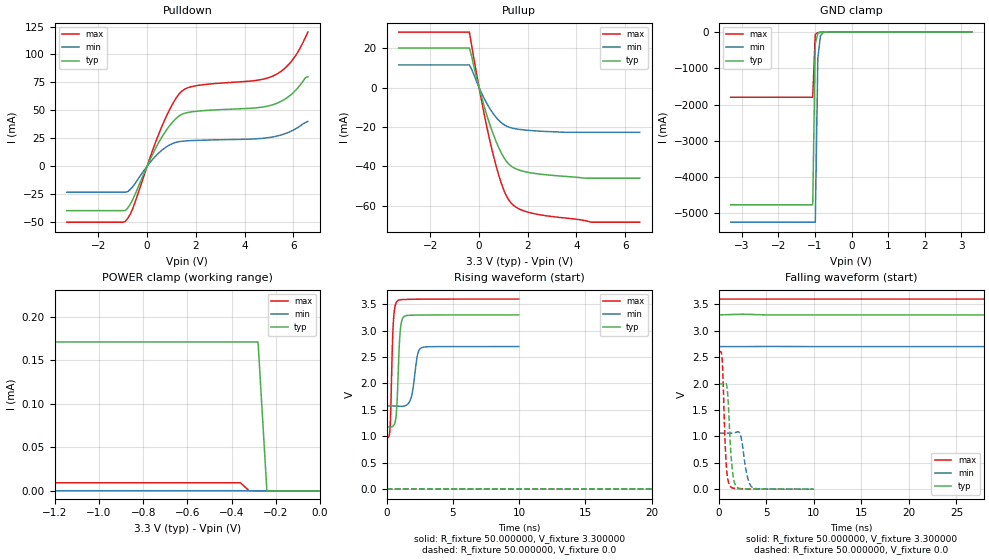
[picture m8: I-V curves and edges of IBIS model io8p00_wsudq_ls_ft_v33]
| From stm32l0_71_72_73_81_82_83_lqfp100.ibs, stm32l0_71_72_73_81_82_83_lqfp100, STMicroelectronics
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|   Model io8p00_wsudq_ls_ft_v33
[Model]  io8p00_wsudq_ls_ft_v33
Model_type I/O
Polarity   Non-Inverting
Enable   Active-Low
Vinl =   0.990000V
Vinh =   2.310000V
Vmeas =  1.650000V
Cref =   50.000000pF
Rref =   100.000000M
Vref =   0.0V
C_comp   2.653200pF   2.620200pF   2.695100pF
[Temperature Range]   25.000000   0.125000k   -40.000000
[Pullup Reference]   3.300000V   2.700000V   3.600000V
[Pulldown Reference]   0.0V   0.0V   0.0V
[POWER Clamp Reference]   3.300000V   2.700000V   3.600000V
[GND Clamp Reference]   0.0V   0.0V   0.0V
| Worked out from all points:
|   slope of the pulldown table from 0 to 0.495 V, typ, clamps not added: 22.6 ohm
|   slope of the pullup table from 0 to 0.495 V, typ, clamps not added: 23.9 ohm
|   GND clamp passes 1 mA (typ) near -0.64 V on its own axis
|   POWER clamp passes 1 mA (typ) near -2.99 V on its own axis
|   rising waveform, R_fixture 50.000000, V_fixture 3.300000: 20-80 % time 214ps typ, 362ps min, 178ps max; typ from 1.18 V to 3.3 V
|   rising waveform, R_fixture 50.000000, V_fixture 0.0: 20-80 % time 204ns typ, 426ns min, 99.2ns max; typ from 0 V to 1.99 V
|   falling waveform, R_fixture 50.000000, V_fixture 3.300000: 20-80 % time 191ns typ, 378ns min, 105ns max; typ from 3.3 V to 1.18 V
|   falling waveform, R_fixture 50.000000, V_fixture 0.0: 20-80 % time 397ps typ, 566ps min, 319ps max; typ from 1.99 V to 0 V
[Pulldown]
|Voltage   I(typ)   I(min)   I(max)
-3.3V     -39.83mA   -23.36mA   -50.2mA
-900mV    -39.83mA   -23.36mA   -49.53mA
-600mV    -30.28mA   -18.58mA   -38.45mA
100mV     4.866mA    2.82mA     6.48mA
600mV     25.85mA    14.17mA    35.39mA
1V        38.33mA    19.81mA    53.88mA
1.4V      46.1mA     22.17mA    66.71mA
2V        49.06mA    23.01mA    71.92mA
4.4V      52.05mA    24.37mA    76.53mA
5.2V      55.25mA    26.3mA     81.02mA
5.9V      63.82mA    31.16mA    93.17mA
6.6V      80mA       40mA       120mA
[Pullup]
|Voltage   I(typ)   I(min)   I(max)
-3.3V     20.14mA    11.54mA    28.23mA
-400mV    20.14mA    11.54mA    28.23mA
100mV     -4.683mA   -2.741mA   -6.645mA
400mV     -17.2mA    -9.8mA     -24.68mA
600mV     -24.27mA   -13.54mA   -35.11mA
800mV     -30.3mA    -16.51mA   -44.18mA
1V        -35.17mA   -18.65mA   -51.61mA
1.2V      -38.59mA   -19.95mA   -56.76mA
1.4V      -40.56mA   -20.67mA   -59.68mA
2.2V      -43.44mA   -21.87mA   -63.88mA
4.6V      -46mA      -22.71mA   -68.38mA
6.6V      -46mA      -22.71mA   -68.38mA
[GND_clamp]
|Voltage   I(typ)   I(min)   I(max)
-3.3V     -4.766A    -5.244A    -1.797A
-1.06V    -4.766A    -5.244A    -1.797A
-990mV    -326.7mA   -5.244A    -68.05mA
-920mV    -29.09mA   -722.2mA   -11.16mA
-850mV    -6.797mA   -104.4mA   -6.682mA
-780mV    -3.554mA   -17.44mA   -4.265mA
-500mV    -58.08uA   -169.3uA   -34.1uA
3.28V     0A         0A         0A
[POWER_clamp]
|Voltage   I(typ)   I(min)   I(max)
-3.28V    3.05A      15.65uA    3.723A
-3.2V     3.05A      1.687uA    3.723A
-2.96V    269.4uA    209.1nA    3.723A
-2.92V    170.9uA    209.1nA    508.5mA
-2.8V     170.9uA    209.1nA    1.296mA
-2.76V    170.9uA    209.1nA    177.1uA
-2.72V    170.9uA    209.1nA    24.25uA
-2.68V    170.9uA    209.1nA    9.362uA
-360mV    170.9uA    209.1nA    9.362uA
-280mV    170.9uA    209.1nA    0A
-240mV    0A         209.1nA    0A
0V        0A         0A         0A
[Ramp]
| variable   typ   min   max
dV/dt_r  1.19502/0.20345u   0.61296/0.42723u   1.55568/99.10886n
dV/dt_f  1.27296/0.19119u   0.63696/0.37850u   1.57855/0.10495u
R_load = 50.000000
[Rising Waveform]
R_fixture= 50.000000
V_fixture= 3.300000
V_fixture_min= 2.700000
V_fixture_max= 3.600000
|time   V(typ)   V(min)   V(max)
0s        1.176V     1.573V     967.1mV
240.2ps   1.173V     1.574V     1.106V
500.5ps   1.197V     1.574V     3.149V
780.8ps   1.643V     1.571V     3.559V
1.021ns   2.991V     1.568V     3.586V
1.341ns   3.274V     1.573V     3.592V
1.862ns   3.294V     1.742V     3.596V
2.302ns   3.296V     2.512V     3.597V
2.643ns   3.297V     2.679V     3.598V
9.97ns    3.3V       2.7V       3.6V
[Rising Waveform]
R_fixture= 50.000000
V_fixture= 0.0
V_fixture_min= 0.0
V_fixture_max= 0.0
|time   V(typ)   V(min)   V(max)
0s        2.289nV    16.78nV    4.802nV
50.05ns   -29.06uV   -21.76uV   91.84mV
100.1ns   78.36mV    135uV      923.8mV
162.7ns   443.1mV    1.959mV    1.914V
202.7ns   735mV      16.24mV    2.282V
247.7ns   1.047V     48.17mV    2.471V
385.4ns   1.674V     236.3mV    2.581V
518ns     1.893V     470.6mV    2.591V
825.8ns   1.986V     877.5mV    2.593V
1.246us   1.992V     1.062V     2.593V
[Falling Waveform]
R_fixture= 50.000000
V_fixture= 3.300000
V_fixture_min= 2.700000
V_fixture_max= 3.600000
|time   V(typ)   V(min)   V(max)
0s        3.3V       2.7V       3.6V
82.58ns   3.3V       2.7V       3.484V
147.6ns   3.196V     2.7V       2.515V
210.2ns   2.847V     2.697V     1.596V
247.7ns   2.588V     2.686V     1.228V
280.3ns   2.354V     2.668V     1.09V
392.9ns   1.62V      2.547V     995.2mV
493ns     1.335V     2.38V      977.3mV
818.3ns   1.195V     1.798V     967.7mV
1.246us   1.176V     1.573V     967.1mV
[Falling Waveform]
R_fixture= 50.000000
V_fixture= 0.0
V_fixture_min= 0.0
V_fixture_max= 0.0
|time   V(typ)   V(min)   V(max)
0s        1.992V     1.062V     2.593V
380.4ps   1.991V     1.062V     2.449V
660.7ps   2.016V     1.062V     985.9mV
840.8ps   1.972V     1.062V     377.3mV
1.001ns   1.677V     1.062V     159.5mV
1.201ns   941.9mV    1.062V     59.25mV
1.542ns   226.5mV    1.062V     18.96mV
2.022ns   26.9mV     1.088V     9.512mV
3.483ns   3.789mV    42.37mV    2.281mV
9.97ns    2.289nV    16.78nV    4.802nV
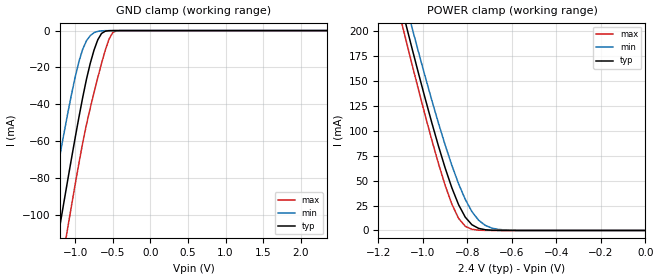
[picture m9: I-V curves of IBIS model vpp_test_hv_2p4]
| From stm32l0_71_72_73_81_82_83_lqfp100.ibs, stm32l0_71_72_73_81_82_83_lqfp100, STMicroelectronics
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|   Model vpp_test_hv_2p4
[Model]  vpp_test_hv_2p4
Model_type Input
Polarity   Non-Inverting
Vinl =   0.720000V
Vinh =   1.680000V
C_comp   1.854600pF   1.841900pF   1.862400pF
[Temperature Range]   25.000000   0.125000k   -40.000000
[Pullup Reference]   2.400000V   1.650000V   2.700000V
[Pulldown Reference]   0.0V   0.0V   0.0V
[POWER Clamp Reference]   2.400000V   1.650000V   2.700000V
[GND Clamp Reference]   0.0V   0.0V   0.0V
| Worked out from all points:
|   GND clamp passes 1 mA (typ) near -0.63 V on its own axis
|   POWER clamp passes 1 mA (typ) near -0.73 V on its own axis
[GND_clamp]
|Voltage   I(typ)   I(min)   I(max)
-2.4V     -403.9mA   -360.4mA   -432.5mA
-1.4V     -153.8mA   -113.7mA   -181mA
-1.35V    -141.6mA   -101.8mA   -168.6mA
-1.25V    -117.2mA   -78.51mA   -143.9mA
-1.2V     -105.1mA   -67.11mA   -131.6mA
-1.1V     -81.29mA   -45.14mA   -107.3mA
-900mV    -36.27mA   -10.07mA   -60.94mA
-750mV    -10.66mA   -1.16mA    -33.72mA
-650mV    -1.571mA   -137.9uA   -17.84mA
-550mV    -63.35uA   -13.87uA   -4.625mA
-450mV    -1.752uA   -1.257uA   -128.5uA
2.35V     0A         0A         0A
[POWER_clamp]
|Voltage   I(typ)   I(min)   I(max)
-2.4V     1.472A     1.477A     1.468A
-1.11V    236.5mA    256mA      221.5mA
-1.08V    209.8mA    229.9mA    194.3mA
-1.05V    183.5mA    204.3mA    167.5mA
-930mV    84.5mA     107.5mA    66.89mA
-870mV    42.69mA    65.24mA    26.3mA
-840mV    25.91mA    46.92mA    12.2mA
-810mV    13.37mA    31.26mA    4.222mA
-750mV    2.125mA    10.31mA    308.7uA
-690mV    253.1uA    2.366mA    21.65uA
-630mV    31.23uA    473.1uA    1.287uA
0V        0A         0A         0A
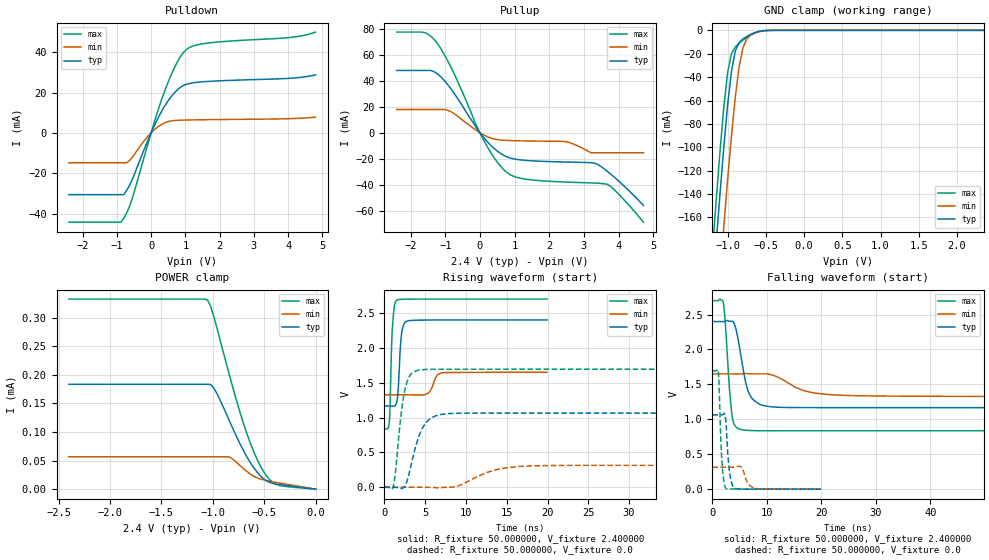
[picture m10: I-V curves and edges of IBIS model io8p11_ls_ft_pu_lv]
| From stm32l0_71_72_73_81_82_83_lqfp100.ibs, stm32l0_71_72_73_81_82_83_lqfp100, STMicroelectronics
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|   Model io8p11_ls_ft_pu_lv
[Model]  io8p11_ls_ft_pu_lv
Model_type I/O
Polarity   Non-Inverting
Enable   Active-Low
Vinl =   0.720000V
Vinh =   1.680000V
Vmeas =  1.200000V
Cref =   50.000000pF
Rref =   100.000000M
Vref =   0.0V
C_comp   4.521100pF   4.438000pF   4.578000pF
[Temperature Range]   25.000000   0.105000k   -40.000000
[Pullup Reference]   2.400000V   1.650000V   2.700000V
[Pulldown Reference]   0.0V   0.0V   0.0V
[POWER Clamp Reference]   2.400000V   1.650000V   2.700000V
[GND Clamp Reference]   0.0V   0.0V   0.0V
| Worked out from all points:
|   slope of the pulldown table from 0 to 0.36 V, typ, clamps not added: 29.5 ohm
|   slope of the pullup table from 0 to 0.36 V, typ, clamps not added: 33.2 ohm
|   GND clamp passes 1 mA (typ) near -0.59 V on its own axis
|   rising waveform, R_fixture 50.000000, V_fixture 2.400000: 20-80 % time 363ps typ, 687ps min, 303ps max; typ from 1.17 V to 2.4 V
|   rising waveform, R_fixture 50.000000, V_fixture 0.0: 20-80 % time 1.62ns typ, 3.85ns min, 982ps max; typ from 0.001 V to 1.06 V
|   falling waveform, R_fixture 50.000000, V_fixture 2.400000: 20-80 % time 1.82ns typ, 5.27ns min, 981ps max; typ from 2.4 V to 1.17 V
|   falling waveform, R_fixture 50.000000, V_fixture 0.0: 20-80 % time 630ps typ, 1.02ns min, 525ps max; typ from 1.06 V to 0.001 V
[Pulldown]
|Voltage   I(typ)   I(min)   I(max)
-2.4V     -30.64mA   -14.84mA   -44.29mA
-880mV    -30.64mA   -14.84mA   -44.29mA
-800mV    -30.64mA   -14.84mA   -42.37mA
-720mV    -28.74mA   -14.84mA   -39.91mA
-560mV    -23.52mA   -12.34mA   -33.09mA
0V        -765nA     -61nA      -2.526uA
400mV     13.38mA    4.998mA    20.91mA
720mV     20.62mA    6.178mA    33.69mA
1.04V     24.19mA    6.384mA    41.49mA
1.6V      25.46mA    6.544mA    44.42mA
4V        27.03mA    7.028mA    47.23mA
4.8V      28.76mA    7.817mA    49.99mA
[Pullup]
|Voltage   I(typ)   I(min)   I(max)
-2.4V     48.08mA    17.96mA    77.62mA
-1.6V     48.08mA    17.96mA    77.24mA
-1.28V    46.46mA    17.96mA    70.59mA
-880mV    35.41mA    16.81mA    52.86mA
160mV     -5.285mA   -2.324mA   -8.223mA
480mV     -13.62mA   -5.102mA   -21.86mA
800mV     -18.73mA   -5.909mA   -31mA
1.28V     -21.13mA   -6.236mA   -35.54mA
2.48V     -22.51mA   -6.818mA   -37.93mA
3.36V     -23.83mA   -15.36mA   -38.77mA
3.76V     -31.49mA   -15.36mA   -41.07mA
4.72V     -56mA      -15.36mA   -68.86mA
[GND_clamp]
|Voltage   I(typ)   I(min)   I(max)
-2.4V     -1.379A    -1.445A    -1.35A
-1.2V     -225.9mA   -297.5mA   -189.2mA
-1.15V    -182mA     -253.1mA   -145.3mA
-1.1V     -139.6mA   -209.7mA   -103.5mA
-1.05V    -99.61mA   -167.6mA   -65.7mA
-1V       -63.67mA   -127.3mA   -35.89mA
-950mV    -35mA      -89.93mA   -19.87mA
-900mV    -17.67mA   -57.01mA   -14.12mA
-850mV    -10.49mA   -31.18mA   -11mA
-750mV    -5.288mA   -7.322mA   -5.997mA
-450mV    -33.57uA   -87.56uA   -14.35uA
2.35V     0A         0A         0A
[POWER_clamp]
|Voltage   I(typ)   I(min)   I(max)
-2.4V     183.5uA    56.67uA    332.6uA
-1.05V    183.5uA    56.67uA    330.7uA
-1.02V    183.2uA    56.67uA    319.4uA
-960mV    167.5uA    56.67uA    282.5uA
-840mV    120.2uA    56.67uA    200.6uA
-750mV    84.84uA    43.79uA    143.2uA
-690mV    63.63uA    34.11uA    108.8uA
-600mV    37.11uA    22.45uA    64.86uA
-510mV    18.78uA    16.35uA    32.08uA
-450mV    12.09uA    14.02uA    17.37uA
-360mV    8.168uA    11.12uA    6.844uA
0V        0A         0A         0A
[Ramp]
| variable   typ   min   max
dV/dt_r  0.63803/1.61692n   0.18819/3.84128n   1.01570/0.97705n
dV/dt_f  0.73962/1.81572n   0.19158/5.26365n   1.11751/0.97777n
R_load = 50.000000
[Rising Waveform]
R_fixture= 50.000000
V_fixture= 2.400000
V_fixture_min= 1.650000
V_fixture_max= 2.700000
|time   V(typ)   V(min)   V(max)
0s        1.167V     1.327V     836.7mV
600.6ps   1.166V     1.327V     939.5mV
961ps     1.163V     1.327V     2.257V
1.481ns   1.212V     1.327V     2.68V
1.682ns   1.392V     1.327V     2.69V
2.082ns   2.18V      1.327V     2.695V
2.683ns   2.378V     1.326V     2.698V
5.205ns   2.399V     1.34V      2.699V
7.047ns   2.4V       1.64V      2.7V
19.94ns   2.4V       1.65V      2.7V
[Rising Waveform]
R_fixture= 50.000000
V_fixture= 0.0
V_fixture_min= 0.0
V_fixture_max= 0.0
|time   V(typ)   V(min)   V(max)
0s        967.8uV    1.355mV    1.069mV
1.126ns   754.8uV    1.352mV    32.46mV
2.002ns   -18.87mV   1.365mV    1.008V
2.503ns   15.57mV    1.441mV    1.394V
3.128ns   249.2mV    1.438mV    1.604V
4.129ns   698.7mV    1.399mV    1.678V
5.631ns   985.5mV    -1.19mV    1.692V
8.258ns   1.059V     2.625mV    1.693V
16.64ns   1.064V     299.8mV    1.693V
62.31ns   1.064V     315mV      1.693V
[Falling Waveform]
R_fixture= 50.000000
V_fixture= 2.400000
V_fixture_min= 1.650000
V_fixture_max= 2.700000
|time   V(typ)   V(min)   V(max)
0s        2.4V       1.65V      2.7V
2.002ns   2.399V     1.65V      2.674V
2.377ns   2.402V     1.65V      2.376V
3.128ns   2.405V     1.65V      1.449V
3.629ns   2.402V     1.65V      1.045V
4.88ns    2.077V     1.65V      864.4mV
6.757ns   1.368V     1.652V     841.1mV
9.885ns   1.19V      1.65V      837.2mV
20.9ns    1.168V     1.357V     836.8mV
62.31ns   1.167V     1.327V     836.7mV
[Falling Waveform]
R_fixture= 50.000000
V_fixture= 0.0
V_fixture_min= 0.0
V_fixture_max= 0.0
|time   V(typ)   V(min)   V(max)
0s        1.064V     315mV      1.693V
1.121ns   1.064V     315mV      1.67V
1.522ns   1.064V     315mV      774.7mV
1.762ns   1.065V     315mV      395.5mV
2.482ns   975.1mV    315mV      14.65mV
3.163ns   242.8mV    314.7mV    3.356mV
4.124ns   16.74mV    318mV      2.241mV
5.285ns   2.962mV    320.8mV    1.565mV
7.928ns   1.476mV    11.82mV    1.181mV
19.94ns   967.8uV    1.355mV    1.069mV
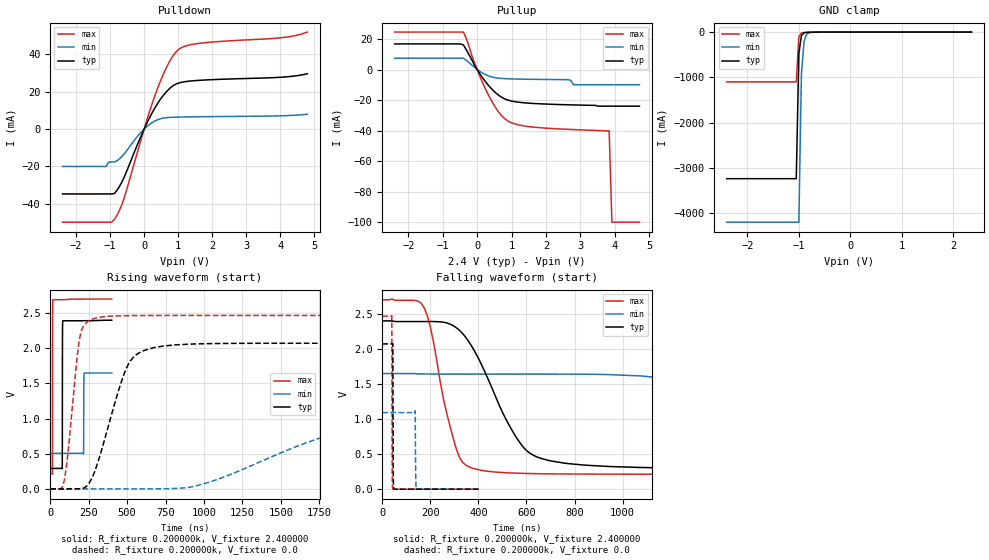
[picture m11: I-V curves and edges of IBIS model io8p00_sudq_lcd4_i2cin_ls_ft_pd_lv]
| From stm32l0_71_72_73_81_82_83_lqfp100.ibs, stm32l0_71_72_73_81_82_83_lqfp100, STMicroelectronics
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|   Model io8p00_sudq_lcd4_i2cin_ls_ft_pd_lv
[Model]  io8p00_sudq_lcd4_i2cin_ls_ft_pd_lv
Model_type I/O
Polarity   Non-Inverting
Enable   Active-Low
Vinl =   0.720000V
Vinh =   1.680000V
Vmeas =  1.200000V
Cref =   50.000000pF
Rref =   100.000000M
Vref =   0.0V
C_comp   2.470900pF   2.435200pF   2.490500pF
[Temperature Range]   25.000000   0.105000k   -40.000000
[Pullup Reference]   2.400000V   1.650000V   2.700000V
[Pulldown Reference]   0.0V   0.0V   0.0V
[POWER Clamp Reference]   2.400000V   1.650000V   2.700000V
[GND Clamp Reference]   0.0V   0.0V   0.0V
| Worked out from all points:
|   slope of the pulldown table from 0 to 0.36 V, typ, clamps not added: 28.5 ohm
|   slope of the pullup table from 0 to 0.36 V, typ, clamps not added: 32.2 ohm
|   GND clamp passes 1 mA (typ) near -0.64 V on its own axis
|   rising waveform, R_fixture 0.200000k, V_fixture 2.400000: 20-80 % time 679ps typ, 852ps min, 746ps max; typ from 0.291 V to 2.4 V
|   rising waveform, R_fixture 0.200000k, V_fixture 0.0: 20-80 % time 169ns typ, 820ns min, 66.4ns max; typ from 0 V to 2.07 V
|   falling waveform, R_fixture 0.200000k, V_fixture 2.400000: 20-80 % time 181ns typ, 729ns min, 89.9ns max; typ from 2.4 V to 0.291 V
|   falling waveform, R_fixture 0.200000k, V_fixture 0.0: 20-80 % time 1.12ns typ, 1.65ns min, 919ps max; typ from 2.07 V to 0 V
[Pulldown]
|Voltage   I(typ)   I(min)   I(max)
-2.4V     -34.7mA    -20mA      -49.82mA
-1.12V    -34.7mA    -20mA      -49.82mA
-1.04V    -34.7mA    -17.6mA    -49.82mA
-880mV    -34.55mA   -17.6mA    -48.46mA
-560mV    -24.65mA   -12.68mA   -35.33mA
0V        326fA      0A         16fA
400mV     13.84mA    5.066mA    22.03mA
720mV     21.25mA    6.254mA    35.26mA
1.04V     24.83mA    6.464mA    43.03mA
1.6V      26.11mA    6.627mA    45.88mA
4V        27.76mA    7.125mA    48.88mA
4.8V      29.64mA    7.94mA     51.96mA
[Pullup]
|Voltage   I(typ)   I(min)   I(max)
-2.4V     16.75mA    7.419mA    24.5mA
-400mV    16.1mA     7.419mA    24.5mA
0V        0A         0A         0A
320mV     -10.16mA   -4.078mA   -16.34mA
640mV     -17.08mA   -5.718mA   -28.28mA
960mV     -20.45mA   -6.128mA   -34.5mA
1.76V     -22.39mA   -6.47mA    -37.97mA
2.64V     -23.11mA   -6.7mA     -39.19mA
2.8V      -23.2mA    -10mA      -39.35mA
3.84V     -24mA      -10mA      -40.2mA
3.92V     -24mA      -10mA      -100mA
4.72V     -24mA      -10mA      -100mA
[GND_clamp]
|Voltage   I(typ)   I(min)   I(max)
-2.4V     -3.237A    -4.197A    -1.1A
-1.05V    -3.237A    -4.197A    -1.1A
-1V       -475.5mA   -4.197A    -104.1mA
-950mV    -76.09mA   -935.1mA   -18.45mA
-900mV    -16.59mA   -212.6mA   -9.272mA
-850mV    -6.633mA   -50.89mA   -6.773mA
-800mV    -4.105mA   -13.86mA   -5.003mA
-650mV    -1.082mA   -1.227mA   -1.183mA
2.35V     52.69uA    50.02uA    36.84uA
[POWER_clamp]
|Voltage   I(typ)   I(min)   I(max)
-2.4V     0A         0A         0A
0V        0A         0A         0A
[Ramp]
| variable   typ   min   max
dV/dt_r  0.65004/0.30183u   0.18965/0.80848u   1.03746/0.14372u
dV/dt_f  0.75702/0.32176u   0.19716/0.84609u   1.13800/0.15972u
R_load = 50.000000
[Rising Waveform]
R_fixture= 0.200000k
V_fixture= 2.400000
V_fixture_min= 1.650000
V_fixture_max= 2.700000
|time   V(typ)   V(min)   V(max)
0s        290.6mV    505.5mV    212.8mV
14.01ns   290.6mV    505.5mV    220mV
15.22ns   290.6mV    505.5mV    2.437V
17.22ns   290.6mV    505.5mV    2.688V
77.68ns   288.7mV    505.5mV    2.691V
79.28ns   2.081V     505.5mV    2.691V
81.28ns   2.386V     505.5mV    2.691V
216.2ns   2.391V     500.8mV    2.699V
221ns     2.391V     1.644V     2.699V
400ns     2.399V     1.648V     2.699V
[Rising Waveform]
R_fixture= 0.200000k
V_fixture= 0.0
V_fixture_min= 0.0
V_fixture_max= 0.0
|time   V(typ)   V(min)   V(max)
0s        1.677nV    10.25nV    1.28nV
93.43ns   -107uV     10.25nV    142.2mV
200.2ns   1.479mV    10.25nV    2.238V
280.3ns   197.5mV    -23.2uV    2.418V
373.7ns   861.8mV    -23.3uV    2.453V
547.2ns   1.886V     17.5uV     2.465V
934.3ns   2.061V     36.25mV    2.466V
1.895us   2.071V     814.2mV    2.466V
2.816us   2.071V     1.059V     2.466V
13.33us   2.071V     1.091V     2.466V
[Falling Waveform]
R_fixture= 0.200000k
V_fixture= 2.400000
V_fixture_min= 1.650000
V_fixture_max= 2.700000
|time   V(typ)   V(min)   V(max)
0s        2.399V     1.648V     2.699V
160.2ns   2.389V     1.643V     2.655V
200.2ns   2.389V     1.641V     2.305V
253.6ns   2.38V      1.64V      1.297V
320.3ns   2.267V     1.64V      456.6mV
507.2ns   1.046V     1.64V      235.7mV
613.9ns   514mV      1.64V      222.9mV
814.1ns   351.3mV    1.639V     215.2mV
2.803us   290.6mV    564.6mV    212.8mV
13.33us   290.6mV    505.5mV    212.8mV
[Falling Waveform]
R_fixture= 0.200000k
V_fixture= 0.0
V_fixture_min= 0.0
V_fixture_max= 0.0
|time   V(typ)   V(min)   V(max)
0s        2.071V     1.091V     2.466V
39.24ns   2.071V     1.091V     2.47V
40.84ns   2.071V     1.091V     349.3mV
43.64ns   2.069V     1.091V     3.207mV
45.25ns   334.6mV    1.091V     649.2uV
48.05ns   3.896mV    1.091V     305.3uV
136.5ns   25.62uV    1.117V     139uV
138.9ns   25.57uV    195.5mV    139.1uV
142.5ns   25.51uV    3.888mV    139.3uV
400ns     1.677nV    10.25nV    1.28nV
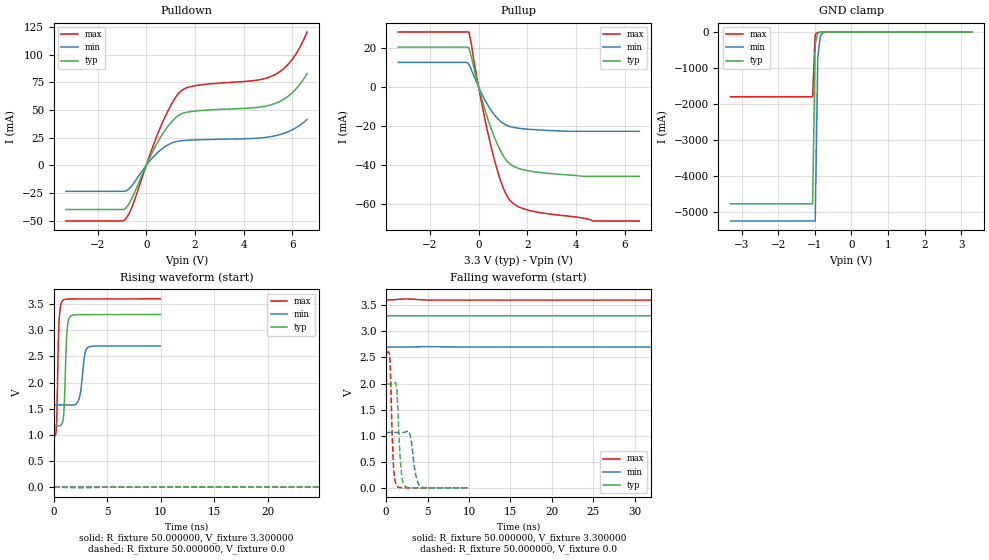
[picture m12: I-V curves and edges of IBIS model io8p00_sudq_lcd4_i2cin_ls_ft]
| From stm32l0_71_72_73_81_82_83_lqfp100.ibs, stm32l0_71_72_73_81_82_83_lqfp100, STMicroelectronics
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|   Model io8p00_sudq_lcd4_i2cin_ls_ft
[Model]  io8p00_sudq_lcd4_i2cin_ls_ft
Model_type I/O
Polarity   Non-Inverting
Enable   Active-Low
Vinl =   0.990000V
Vinh =   2.310000V
Vmeas =  1.650000V
Cref =   50.000000pF
Rref =   100.000000M
Vref =   0.0V
C_comp   2.499500pF   2.460800pF   2.557800pF
[Temperature Range]   25.000000   0.125000k   -40.000000
[Pullup Reference]   3.300000V   2.700000V   3.600000V
[Pulldown Reference]   0.0V   0.0V   0.0V
[POWER Clamp Reference]   3.300000V   2.700000V   3.600000V
[GND Clamp Reference]   0.0V   0.0V   0.0V
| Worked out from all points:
|   slope of the pulldown table from 0 to 0.495 V, typ, clamps not added: 22.6 ohm
|   slope of the pullup table from 0 to 0.495 V, typ, clamps not added: 23.9 ohm
|   GND clamp passes 1 mA (typ) near -0.64 V on its own axis
|   rising waveform, R_fixture 50.000000, V_fixture 3.300000: 20-80 % time 216ps typ, 365ps min, 176ps max; typ from 1.18 V to 3.3 V
|   rising waveform, R_fixture 50.000000, V_fixture 0.0: 20-80 % time 203ns typ, 423ns min, 99.1ns max; typ from 0 V to 1.99 V
|   falling waveform, R_fixture 50.000000, V_fixture 3.300000: 20-80 % time 191ns typ, 381ns min, 105ns max; typ from 3.3 V to 1.18 V
|   falling waveform, R_fixture 50.000000, V_fixture 0.0: 20-80 % time 383ps typ, 551ps min, 305ps max; typ from 1.99 V to 0 V
[Pulldown]
|Voltage   I(typ)   I(min)   I(max)
-3.3V     -39.83mA   -23.37mA   -50.2mA
-900mV    -39.83mA   -23.37mA   -49.53mA
-600mV    -30.28mA   -18.59mA   -38.45mA
500mV     22.11mA    12.28mA    30.1mA
1V        38.33mA    19.81mA    53.88mA
1.4V      46.1mA     22.18mA    66.72mA
2V        49.07mA    23.01mA    71.93mA
4.4V      52.05mA    24.38mA    76.53mA
5.2V      55.25mA    26.3mA     81.02mA
5.6V      59.18mA    28.57mA    86.57mA
6V        65.78mA    32.24mA    95.96mA
6.6V      82.83mA    41.41mA    120.4mA
[Pullup]
|Voltage   I(typ)   I(min)   I(max)
-3.3V     20.52mA    12.64mA    28.28mA
-400mV    20.25mA    11.77mA    28.28mA
-300mV    15.65mA    8.927mA    22.43mA
-200mV    10.4mA     5.943mA    13.84mA
100mV     -4.685mA   -2.744mA   -6.647mA
600mV     -24.29mA   -13.56mA   -35.12mA
1V        -35.2mA    -18.69mA   -51.63mA
1.2V      -38.62mA   -19.99mA   -56.79mA
1.4V      -40.6mA    -20.72mA   -59.71mA
2.2V      -43.48mA   -21.92mA   -63.91mA
4.7V      -46mA      -22.8mA    -69mA
6.6V      -46mA      -22.8mA    -69mA
[GND_clamp]
|Voltage   I(typ)   I(min)   I(max)
-3.3V     -4.766A    -5.244A    -1.797A
-1.06V    -4.766A    -5.244A    -1.797A
-990mV    -326.4mA   -5.244A    -67.85mA
-920mV    -28.83mA   -721.7mA   -11.08mA
-850mV    -6.686mA   -104.1mA   -6.707mA
-780mV    -3.552mA   -17.28mA   -4.326mA
-500mV    -59.41uA   -172uA     -34.91uA
3.28V     0A         0A         0A
[POWER_clamp]
|Voltage   I(typ)   I(min)   I(max)
-3.28V    0A         0A         0A
0V        0A         0A         0A
[Ramp]
| variable   typ   min   max
dV/dt_r  1.19496/0.20326u   0.61278/0.42530u   1.55568/99.01306n
dV/dt_f  1.27296/0.19086u   0.63678/0.38112u   1.57856/0.10500u
R_load = 50.000000
[Rising Waveform]
R_fixture= 50.000000
V_fixture= 3.300000
V_fixture_min= 2.700000
V_fixture_max= 3.600000
|time   V(typ)   V(min)   V(max)
0s        1.177V     1.573V     967.3mV
240.2ps   1.175V     1.573V     1.143V
520.5ps   1.173V     1.574V     3.264V
800.8ps   1.233V     1.574V     3.561V
961ps     1.503V     1.574V     3.586V
1.221ns   2.945V     1.572V     3.595V
1.542ns   3.266V     1.568V     3.597V
2.382ns   3.298V     1.703V     3.599V
3.203ns   3.299V     2.674V     3.599V
9.97ns    3.3V       2.7V       3.6V
[Rising Waveform]
R_fixture= 50.000000
V_fixture= 0.0
V_fixture_min= 0.0
V_fixture_max= 0.0
|time   V(typ)   V(min)   V(max)
0s        2.052nV    14.28nV    4.455nV
47.55ns   328.5uV    -21.67uV   62.39mV
100.1ns   75.39mV    5.959uV    913.9mV
165.2ns   455.6mV    5.329mV    1.937V
205.2ns   748.4mV    15.7mV     2.294V
252.8ns   1.075V     52.1mV     2.48V
387.9ns   1.679V     239.2mV    2.58V
538ns     1.911V     504.5mV    2.591V
883.4ns   1.988V     922.4mV    2.592V
1.246us   1.992V     1.062V     2.592V
[Falling Waveform]
R_fixture= 50.000000
V_fixture= 3.300000
V_fixture_min= 2.700000
V_fixture_max= 3.600000
|time   V(typ)   V(min)   V(max)
0s        3.3V       2.7V       3.6V
82.58ns   3.3V       2.7V       3.49V
150.2ns   3.19V      2.7V       2.486V
212.7ns   2.837V     2.697V     1.575V
250.2ns   2.578V     2.686V     1.217V
290.3ns   2.289V     2.661V     1.072V
395.4ns   1.613V     2.545V     994.2mV
498ns     1.331V     2.372V     976.8mV
868.4ns   1.192V     1.747V     967.7mV
1.246us   1.177V     1.573V     967.3mV
[Falling Waveform]
R_fixture= 50.000000
V_fixture= 0.0
V_fixture_min= 0.0
V_fixture_max= 0.0
|time   V(typ)   V(min)   V(max)
0s        1.992V     1.062V     2.592V
440.4ps   1.992V     1.062V     2.502V
860.9ps   1.996V     1.062V     491.5mV
1.261ns   1.913V     1.062V     44.66mV
1.762ns   426.9mV    1.061V     4.266mV
2.222ns   40.2mV     1.065V     1.712mV
2.883ns   2.719mV    1.023V     1.023mV
3.504ns   1.027mV    307.9mV    693.4uV
4.164ns   613.4uV    23.13mV    472.5uV
9.97ns    2.052nV    14.28nV    4.455nV
